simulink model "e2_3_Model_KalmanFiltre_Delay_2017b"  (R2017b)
settings: Solver=ode4  StartTime=0.0  StopTime=100  FixedStep=sampleTime  RelTol=1e-3  EnableMultiTasking=on
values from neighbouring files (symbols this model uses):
  k_d_x = 0.7    [startSimulation.m]
  k_d_y = 0.7    [startSimulation.m]
  k_d_yaw = 0.05    [startSimulation.m]
  k_d_z = 0.05    [startSimulation.m]
  k_i_x = 0.01    [startSimulation.m]
  k_i_y = 0.01    [startSimulation.m]
  k_i_yaw = 0.01    [startSimulation.m]
  k_i_z = 0.01    [startSimulation.m]
  k_p_x = 1    [startSimulation.m]
  k_p_y = 1    [startSimulation.m]
  k_p_yaw = 2    [startSimulation.m]
  k_p_z = 3    [startSimulation.m]
  Kd_RP_AgngleRate = 0.005    [startSimulation.m]
  Kd_YAW_AngleRate = 0.05    [startSimulation.m]
  Ki_RP_AgngleRate = 0.01    [startSimulation.m]
  Ki_YAW_AngleRate = 0.8    [startSimulation.m]
  Kp_RP_AgngleRate = 0.55    [startSimulation.m]
  Kp_RP_ANGLE = 6.5    [startSimulation.m]
  Kp_YAW_AngleRate = 3.2    [startSimulation.m]
  saturation_psi = 2    [startSimulation.m]
  saturation_x = 2    [startSimulation.m]
  saturation_y = 2    [startSimulation.m]
  saturation_z = 2    [startSimulation.m]
  simDT = 0.01    [startSimulation.m]
undefined symbols (not defined in the file or in its folder): DiscIntNeverNeededParam, Earth, earthRadius, KiPitchAttitude, KiRollAttitude, ModelInit, ModelParam, Receive, Send, sigbuilder_block, unidrnd, WGS84
libraries: simulink x26, sharedtransform x3, aerolibtransform2 x3, aerolibfltsims x3, aerolibutil x2, aerolibanimutils x1, shared6dof x1, aerolibatmos2 x1, aerolibconvert2 x1, aerolibobsolete x1, aerolibasang x1, aerolibnav x1
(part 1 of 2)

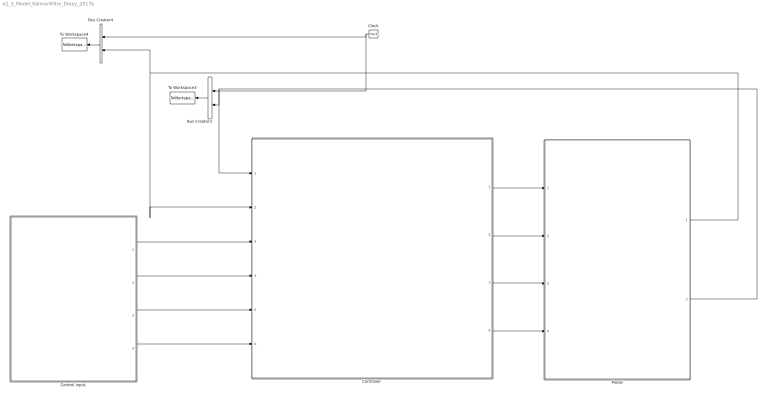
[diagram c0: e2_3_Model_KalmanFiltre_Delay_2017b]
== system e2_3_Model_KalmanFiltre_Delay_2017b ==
  Bus Creator3 : BusCreator  Inputs=2
  Bus Creator4 : BusCreator  Inputs=2
  Clock : Clock
  Control Input : Subsystem
  "Controller " : Subsystem
  Model : Subsystem
  To Workspace3 : ToWorkspace  VariableName=r1_pos_array  SampleTime=-1
  To Workspace4 : ToWorkspace  VariableName=r1_vel_array  SampleTime=-1
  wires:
  Clock/1 -> Bus Creator4/1, Bus Creator3/1
  Bus Creator3/1 -> To Workspace3/1
  Bus Creator4/1 -> To Workspace4/1
  "Controller "/1(Controller Output X) -> Model/1(Commande Input X)
  "Controller "/2(Controller Output Y) -> Model/2(Commande Input Y)
  "Controller "/3(Controller Output H) -> Model/3(Commande Input H)
  "Controller "/4(Controller Output Psi) -> Model/4(Commande Input Psi)
  Control Input/1(ux) -> "Controller "/3(Control input X)
  Control Input/2(uy) -> "Controller "/4(Control input Y)
  Control Input/3(uz) -> "Controller "/5(Control input H)
  Control Input/4(upsi) -> "Controller "/6(Control input Psi)
  Model/2(Output Position) -> "Controller "/1(Feedback Position), Bus Creator3/2
  Model/1(Output Velocity) -> "Controller "/2(Feedback Velocity), Bus Creator4/2

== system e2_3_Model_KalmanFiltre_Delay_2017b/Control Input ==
  Bloc Test Position Fixe : Subsystem
  Bus Creator : BusCreator  Inputs=4
  Demux : Demux
  Simulation Pace : aerolibanimutils/Simulation Pace  SimulationPace=1  SleepMode=MATLAB Thread  OutputPaceError=off  SampleTime=-1
  ux : Outport  VectorParamsAs1DForOutWhenUnconnected=off
  uy : Outport  Port=2  VectorParamsAs1DForOutWhenUnconnected=off
  uz : Outport  Port=3  VectorParamsAs1DForOutWhenUnconnected=off
  upsi : Outport  Port=4  VectorParamsAs1DForOutWhenUnconnected=off
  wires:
  Demux/2 -> uy/1
  Demux/1 -> ux/1
  Bloc Test Position Fixe/2(uy) -> Bus Creator/2
  Demux/3 -> uz/1
  Demux/4 -> upsi/1
  Bloc Test Position Fixe/4(upsi) -> Bus Creator/4
  Bloc Test Position Fixe/3(uz) -> Bus Creator/3
  Bloc Test Position Fixe/1(ux) -> Bus Creator/1
  Bus Creator/1 -> Demux/1

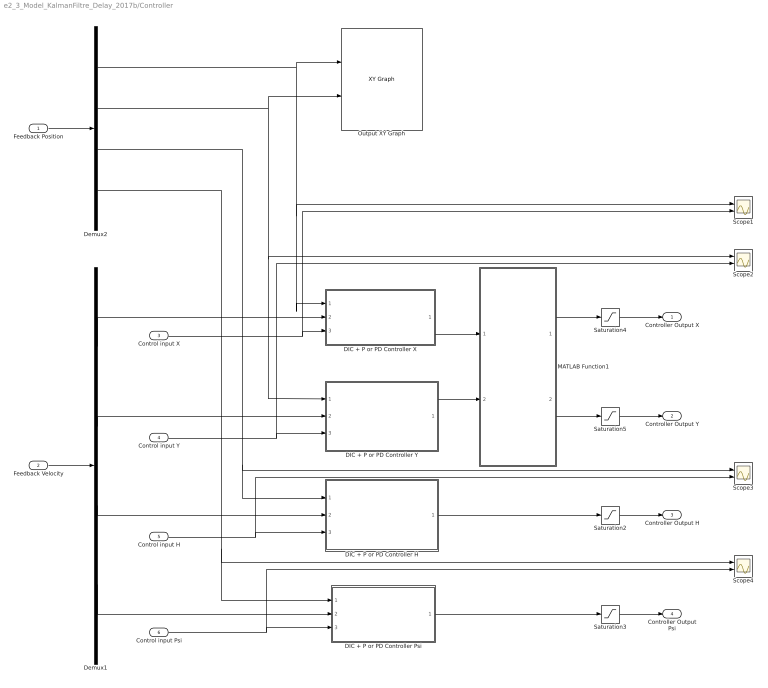
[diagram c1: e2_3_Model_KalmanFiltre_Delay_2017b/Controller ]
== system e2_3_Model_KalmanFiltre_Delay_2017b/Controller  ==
  Feedback Position : Inport
  Feedback Velocity : Inport  Port=2
  Control input X : Inport  Port=3
  Control input Y : Inport  Port=4
  Control input H : Inport  Port=5
  Control input Psi : Inport  Port=6
  DIC + P or PD Controller H : Subsystem
  DIC + P or PD Controller Psi : Subsystem
  DIC + P or PD Controller X : Subsystem
  DIC + P or PD Controller Y : Subsystem
  Demux1 : Demux
  Demux2 : Demux
  MATLAB Function1 : MATLAB Function  TreatAsAtomicUnit=on
  Output XY Graph : simulink/Sinks/XY Graph  Commented=on  xmin=-5  xmax=5  ymin=-5  ymax=5  st=-1
  Saturation2 : Saturate  UpperLimit=saturation_z  LowerLimit=-saturation_z
  Saturation3 : Saturate  UpperLimit=saturation_psi  LowerLimit=-saturation_psi
  Saturation4 : Saturate  UpperLimit=saturation_x  LowerLimit=-saturation_x
  Saturation5 : Saturate  UpperLimit=saturation_y  LowerLimit=-saturation_y
  Scope{1..4} (4 alike) : Scope  NumInputPorts=2
  Controller Output X : Outport  VectorParamsAs1DForOutWhenUnconnected=off
  Controller Output Y : Outport  Port=2  VectorParamsAs1DForOutWhenUnconnected=off
  Controller Output H : Outport  Port=3  VectorParamsAs1DForOutWhenUnconnected=off
  Controller Output Psi : Outport  Port=4  VectorParamsAs1DForOutWhenUnconnected=off
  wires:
  Feedback Position/1 -> Demux2/1
  Feedback Velocity/1 -> Demux1/1
  Demux1/2 -> DIC + P or PD Controller Y/2(Feedback Velocity Y)
  Demux2/3 -> Scope3/1, DIC + P or PD Controller H/1(Feedback Position H)
  Demux1/1 -> DIC + P or PD Controller X/2(Feedback Velocity X)
  Demux1/3 -> DIC + P or PD Controller H/2(Feedback Velocity H)
  Control input X/1 -> Scope1/2, DIC + P or PD Controller X/3(Control Input X)
  Control input H/1 -> Scope3/2, DIC + P or PD Controller H/3(Control Input H)
  Saturation4/1 -> Controller Output X/1
  Saturation5/1 -> Controller Output Y/1
  Saturation2/1 -> Controller Output H/1
  Saturation3/1 -> Controller Output Psi/1
  Control input Y/1 -> Scope2/2, DIC + P or PD Controller Y/3(Control Input Y)
  DIC + P or PD Controller H/1(Controller Output H) -> Saturation2/1
  DIC + P or PD Controller Psi/1(Controller Output Psi) -> Saturation3/1
  Demux2/1 -> Scope1/1, DIC + P or PD Controller X/1(Feedback Position X), Output XY Graph/1
  Demux2/2 -> Scope2/1, DIC + P or PD Controller Y/1(Feedback Position Y), Output XY Graph/2
  Demux2/4 -> Scope4/1, DIC + P or PD Controller Psi/1(Feedback Position Psi)
  Demux1/4 -> DIC + P or PD Controller Psi/2(Feedback Velocity Psi)
  Control input Psi/1 -> Scope4/2, DIC + P or PD Controller Psi/3(Control input Psi)
  MATLAB Function1/2(phi) -> Saturation5/1
  MATLAB Function1/1(theta) -> Saturation4/1
  DIC + P or PD Controller X/1(Controller Output X) -> MATLAB Function1/1(eax)
  DIC + P or PD Controller Y/1(Controller Output Y) -> MATLAB Function1/2(eay)

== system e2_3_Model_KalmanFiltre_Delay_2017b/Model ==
  Commande Input X : Inport
  Commande Input Y : Inport  Port=2
  Commande Input H : Inport  Port=3
  Commande Input Psi : Inport  Port=4
  Bus Creator5 : BusCreator  Inputs=4
  Demux : Demux
  Demux1 : Demux
  Drone_Model_F450 : Subsystem
  Kalman Filtre H : Subsystem
  Kalman Filtre Psi : Subsystem
  Kalman Filtre X : Subsystem
  Kalman Filtre Y : Subsystem
  Output Velocity : Outport  VectorParamsAs1DForOutWhenUnconnected=off
  Output Position : Outport  Port=2  VectorParamsAs1DForOutWhenUnconnected=off
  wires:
  Demux/4 -> Kalman Filtre Psi/1(The system output: Position)
  Bus Creator5/1 -> Output Velocity/1
  Demux/1 -> Kalman Filtre X/1(The system output: Position)
  Kalman Filtre X/1(Out velocity feedback) -> Bus Creator5/1
  Kalman Filtre Psi/1(Out velocity feedback) -> Bus Creator5/4
  Demux/2 -> Kalman Filtre Y/1(The system output: Position)
  Kalman Filtre Y/1(Out velocity feedback) -> Bus Creator5/2
  Kalman Filtre H/1(Out velocity feedback) -> Bus Creator5/3
  Demux/3 -> Kalman Filtre H/1(The system output: Position)
  Demux1/1 -> Kalman Filtre X/2(In2)
  Demux1/2 -> Kalman Filtre Y/2(In2)
  Demux1/3 -> Kalman Filtre H/2(In2)
  Demux1/4 -> Kalman Filtre Psi/2(In2)
  Commande Input H/1 -> Drone_Model_F450/3(u_Thrust_Z_inM/s)
  Drone_Model_F450/1(Position Feedback in m&rad) -> Output Position/1, Demux/1
  Commande Input Psi/1 -> Drone_Model_F450/4(u_YawRate_Psi_inRad/s)
  Commande Input X/1 -> Drone_Model_F450/1(u_Pitch_Theta_X_inRAD_[-0.5,0.5])
  Commande Input Y/1 -> Drone_Model_F450/2(u_Roll_Phi_Y_inRAD_[-0.5,0.5])
  Drone_Model_F450/2(Velocity Feedback in m/s&rad/s) -> Demux1/1

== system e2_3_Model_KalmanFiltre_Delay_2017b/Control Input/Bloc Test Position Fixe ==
  Band-Limited White Noise : simulink/Sources/Band-Limited White Noise  Cov=[0.01]  Ts=simDT  seed=unidrnd(20000)
  Constant2 : Constant
  Gain : Gain  Gain=0.01
  Signal Builder : Subsystem  Tag=STV Subsys  LoadFcn=sigbuilder_block('load');  StartFcn=sigbuilder_block('start');  StopFcn=sigbuilder_block('stop');  ClipboardFcn=sigbuilder_block('clipboard');  mask(Sigbuilder block){tuvar=[0:10]}
      mask help: Simulink:masks:SigbuilderBlock_MD
      mask init:
      | if ~strcmp(get_param(bdroot(gcbh),'SimulationStatus'),'stopped') tuvar = sigbuilder_block('maskInit'); end
  Sine Wave : Sin  Frequency=0.5  SampleTime=0
  Slider Gain1 : simulink/Math Operations/Slider Gain  gain=1  low=-10  high=10
  Slider Gain2 : simulink/Math Operations/Slider Gain  gain=0  low=-10  high=10
  Slider Gain3 : simulink/Math Operations/Slider Gain  gain=0  low=-2  high=2
  Slider Gain4 : simulink/Math Operations/Slider Gain  gain=0  low=-2  high=2
  Step : Step  Time=5  SampleTime=0
  Sum : Sum  Inputs=|++
  Sum1 : Sum  Inputs=|++
  ux : Outport  VectorParamsAs1DForOutWhenUnconnected=off
  uy : Outport  Port=2  VectorParamsAs1DForOutWhenUnconnected=off
  uz : Outport  Port=3  VectorParamsAs1DForOutWhenUnconnected=off
  upsi : Outport  Port=4  VectorParamsAs1DForOutWhenUnconnected=off
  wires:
  Slider Gain1/1 -> ux/1
  Slider Gain2/1 -> uy/1
  Slider Gain3/1 -> uz/1
  Slider Gain4/1 -> upsi/1
  Sum/1 -> Slider Gain3/1
  Constant2/1 -> Sum/1
  Band-Limited White Noise/1 -> Gain/1
  Sine Wave/1 -> Sum1/1
  Gain/1 -> Sum1/2
  Sum1/1 -> Slider Gain2/1, Slider Gain1/1, Slider Gain4/1, Sum/2

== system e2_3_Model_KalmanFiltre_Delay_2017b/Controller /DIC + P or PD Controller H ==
  Feedback Position H : Inport
  Feedback Velocity H : Inport  Port=2
  Control Input H : Inport  Port=3
  Derivative : Derivative
  Integrator : Integrator
  Sum1 : Sum  Inputs=|-+
  Sum10 : Sum  Inputs=|+-
  Sum9 : Sum  Inputs=+++|
  Vx-d2 : Gain  Gain=k_d_z
  kxp3 : Gain  Gain=k_p_z
  kxp4 : Gain  Gain=k_i_z
  Controller Output H : Outport  VectorParamsAs1DForOutWhenUnconnected=off
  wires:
  Sum9/1 -> Controller Output H/1
  Sum10/1 -> kxp3/1, Integrator/1
  kxp3/1 -> Sum9/2
  Vx-d2/1 -> Sum9/1
  Feedback Velocity H/1 -> Sum1/1
  Sum1/1 -> Vx-d2/1
  Integrator/1 -> kxp4/1
  kxp4/1 -> Sum9/3
  Control Input H/1 -> Sum10/1, Derivative/1
  Feedback Position H/1 -> Sum10/2
  Derivative/1 -> Sum1/2

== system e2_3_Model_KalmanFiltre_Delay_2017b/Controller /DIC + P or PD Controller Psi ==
  Feedback Position Psi : Inport
  Feedback Velocity Psi : Inport  Port=2
  Control input Psi : Inport  Port=3
  Derivative : Derivative
  Gain1 : Gain  Gain=k_p_yaw
  Gain4 : Gain  Gain=k_d_yaw
  Integrator : Integrator
  Sum1 : Sum  Inputs=|-+
  Sum10 : Sum  Inputs=|+-
  Sum9 : Sum  Inputs=+++|
  kxp2 : Gain  Gain=k_i_yaw
  Controller Output Psi : Outport  VectorParamsAs1DForOutWhenUnconnected=off
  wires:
  Sum9/1 -> Controller Output Psi/1
  kxp2/1 -> Sum9/3
  Control input Psi/1 -> Sum10/1, Derivative/1
  Gain4/1 -> Sum9/1
  Sum10/1 -> Gain1/1, Integrator/1
  Integrator/1 -> kxp2/1
  Feedback Velocity Psi/1 -> Sum1/1
  Sum1/1 -> Gain4/1
  Gain1/1 -> Sum9/2
  Derivative/1 -> Sum1/2
  Feedback Position Psi/1 -> Sum10/2

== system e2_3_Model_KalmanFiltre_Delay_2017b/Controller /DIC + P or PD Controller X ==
  Feedback Position X : Inport
  Feedback Velocity X : Inport  Port=2
  Control Input X : Inport  Port=3
  PID1 : Subsystem
  Sum3 : Sum  Inputs=|+-
  Sum4 : Sum  Inputs=|+-
  roll_attitude2 : simulink/Continuous/PID Controller  Controller=P  Form=Parallel  TimeDomain=Discrete-time  SampleTime=-1  IntegratorMethod=Forward Euler  FilterMethod=Forward Euler  ControllerParametersSource=internal  P=1  I=KiRollAttitude  D=0.01  UseFilter=on  N=100  TunerSelectOption=Transfer Function Based (PID Tuner App)  InitialConditionSource=internal  InitialConditionForIntegrator=0  InitialConditionForFilter=0  DifferentiatorICPrevScaledInput=0  ExternalReset=none  TrackingMode=off  Kt=1  LimitOutput=on  UpperSaturationLimit=100  LowerSaturationLimit=-100  LinearizeAsGain=on  AntiWindupMode=back-calculation  Kb=1  POutMin=[]  POutMax=[]  IOutMin=[]  IOutMax=[]  DOutMin=[]  DOutMax=[]  NOutMin=[]  NOutMax=[]  SumOutMin=[]  SumOutMax=[]  SaturationOutMin=[]  SaturationOutMax=[]  PParamMin=[]  PParamMax=[]  IParamMin=[]  IParamMax=[]  DParamMin=[]  DParamMax=[]  NParamMin=[]  NParamMax=[]  KbParamMin=[]  KbParamMax=[]  KtParamMin=[]  KtParamMax=[]  KbOutMin=[]  KbOutMax=[]  KtOutMin=[]  KtOutMax=[]  IntegratorOutMin=[]  IntegratorOutMax=[]  FilterOutMin=[]  FilterOutMax=[]  SumI1OutMin=[]  SumI1OutMax=[]  SumI2OutMin=[]  SumI2OutMax=[]  SumI3OutMin=[]  SumI3OutMax=[]  SumDOutMin=[]  SumDOutMax=[]  DifferentiatorOutMin=[]  DifferentiatorOutMax=[]  FilterDiffOutCoefMin=[]  FilterDiffOutCoefMax=[]  ReciprocalOutMin=[]  ReciprocalOutMax=[]  SumDenOutMin=[]  SumDenOutMax=[]  SumNumOutMin=[]  SumNumOutMax=[]  DivideOutMin=[]  DivideOutMax=[]  IntegratorContinuousStateAttributes=''  IntegratorStateMustResolveToSignalObject=off  IntegratorRTWStateStorageClass=Auto  FilterContinuousStateAttributes=''  FilterStateMustResolveToSignalObject=off  FilterRTWStateStorageClass=Auto  InitialConditionSetting=State (most efficient)
  Controller Output X : Outport  VectorParamsAs1DForOutWhenUnconnected=off
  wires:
  roll_attitude2/1 -> Sum4/1
  Sum3/1 -> roll_attitude2/1
  Sum4/1 -> PID1/1(x)
  PID1/1(y) -> Controller Output X/1
  Feedback Velocity X/1 -> Sum4/2
  Control Input X/1 -> Sum3/1
  Feedback Position X/1 -> Sum3/2

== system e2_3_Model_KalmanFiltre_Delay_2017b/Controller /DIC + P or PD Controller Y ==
  Feedback Position Y : Inport
  Feedback Velocity Y : Inport  Port=2
  Control Input Y : Inport  Port=3
  PID2 : Subsystem
  Sum : Sum  Inputs=|+-
  Sum2 : Sum  Inputs=|+-
  roll_attitude : simulink/Continuous/PID Controller  Controller=P  Form=Parallel  TimeDomain=Discrete-time  SampleTime=-1  IntegratorMethod=Forward Euler  FilterMethod=Forward Euler  ControllerParametersSource=internal  P=1  I=KiRollAttitude  D=0.01  UseFilter=on  N=100  TunerSelectOption=Transfer Function Based (PID Tuner App)  InitialConditionSource=internal  InitialConditionForIntegrator=0  InitialConditionForFilter=0  DifferentiatorICPrevScaledInput=0  ExternalReset=none  TrackingMode=off  Kt=1  LimitOutput=on  UpperSaturationLimit=1  LowerSaturationLimit=-1  LinearizeAsGain=on  AntiWindupMode=back-calculation  Kb=1  POutMin=[]  POutMax=[]  IOutMin=[]  IOutMax=[]  DOutMin=[]  DOutMax=[]  NOutMin=[]  NOutMax=[]  SumOutMin=[]  SumOutMax=[]  SaturationOutMin=[]  SaturationOutMax=[]  PParamMin=[]  PParamMax=[]  IParamMin=[]  IParamMax=[]  DParamMin=[]  DParamMax=[]  NParamMin=[]  NParamMax=[]  KbParamMin=[]  KbParamMax=[]  KtParamMin=[]  KtParamMax=[]  KbOutMin=[]  KbOutMax=[]  KtOutMin=[]  KtOutMax=[]  IntegratorOutMin=[]  IntegratorOutMax=[]  FilterOutMin=[]  FilterOutMax=[]  SumI1OutMin=[]  SumI1OutMax=[]  SumI2OutMin=[]  SumI2OutMax=[]  SumI3OutMin=[]  SumI3OutMax=[]  SumDOutMin=[]  SumDOutMax=[]  DifferentiatorOutMin=[]  DifferentiatorOutMax=[]  FilterDiffOutCoefMin=[]  FilterDiffOutCoefMax=[]  ReciprocalOutMin=[]  ReciprocalOutMax=[]  SumDenOutMin=[]  SumDenOutMax=[]  SumNumOutMin=[]  SumNumOutMax=[]  DivideOutMin=[]  DivideOutMax=[]  IntegratorContinuousStateAttributes=''  IntegratorStateMustResolveToSignalObject=off  IntegratorRTWStateStorageClass=Auto  FilterContinuousStateAttributes=''  FilterStateMustResolveToSignalObject=off  FilterRTWStateStorageClass=Auto  InitialConditionSetting=State (most efficient)
  Controller Output Y : Outport  VectorParamsAs1DForOutWhenUnconnected=off
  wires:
  Sum/1 -> roll_attitude/1
  roll_attitude/1 -> Sum2/1
  Sum2/1 -> PID2/1(x)
  Feedback Position Y/1 -> Sum/2
  Feedback Velocity Y/1 -> Sum2/2
  Control Input Y/1 -> Sum/1
  PID2/1(y) -> Controller Output Y/1

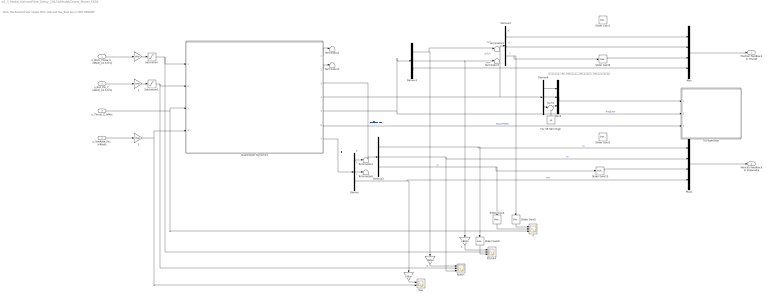
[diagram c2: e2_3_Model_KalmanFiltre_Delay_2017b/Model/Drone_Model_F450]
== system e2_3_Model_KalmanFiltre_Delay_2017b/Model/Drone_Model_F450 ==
  note: 偏航角度值介于[-180,180]之间，超过180度时自动变为-180度之后再继续增加。
  note: Here, the desired Euler angles Pitch, Roll and Yaw_Rate are in UNIT DEGREE!
  note: z
  note: y
  note: x
  note: r
  note: q
  note: p
  note: yaw
  note: pitch
  note: roll
  u_Pitch_Theta_X_inRAD_[-0.5,0.5] : Inport
  u_Roll_Phi_Y_inRAD_[-0.5,0.5] : Inport  Port=2
  u_Thrust_Z_inM/s : Inport  Port=3
  u_YawRate_Psi_inRad/s : Inport  Port=4
  " " : Gain  Gain=180/pi
  "  " : Gain  Gain=180/pi
  "  1" : Gain  Gain=180/pi
  "  2" : Gain  Gain=180/pi
  " 1" : Gain  Gain=180/pi
  " 2" : Gain  Gain=180/pi
  Demux{,1..4} (5 alike) : Demux  Outputs=3
  For VR 50m High : Constant  Value=-50
  Mux : Mux
  Mux1 : Mux
  Mux2 : Mux  Inputs=3
  Pitch&X : Scope  NumInputPorts=3
  Quadcopter Dynamics : Subsystem
  Roll&Y : Scope  NumInputPorts=3
  Saturation : Saturate  UpperLimit=15  LowerLimit=-15
  Saturation1 : Saturate  UpperLimit=15  LowerLimit=-15
  Slider Gain{1..2,4..6,9,13} (7 alike) : simulink/Math Operations/Slider Gain  gain=-1  low=-5  high=5
  Sum1 : Sum  Inputs=|++
  Terminator{1,3..7} (6 alike) : Terminator
  To FlightGear : Subsystem
  Yaw : Scope  NumInputPorts=2
  Z : Scope  NumInputPorts=3
  Position Feedback in m&rad : Outport  VectorParamsAs1DForOutWhenUnconnected=off
  Velocity Feedback in m/s&rad/s : Outport  Port=2  VectorParamsAs1DForOutWhenUnconnected=off
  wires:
  " 2"/1 -> Quadcopter Dynamics/4(u_Yaw_rate), Yaw/2
  "  1"/1 -> Pitch&X/1
  " 1"/1 -> Saturation1/1
  Slider Gain9/1 -> Mux/3
  Slider Gain13/1 -> Mux1/3
  " "/1 -> Saturation/1
  Demux2/2 -> Mux/2
  u_Pitch_Theta_X_inRAD_[-0.5,0.5]/1 -> " "/1
  Slider Gain4/1 -> Z/2
  Demux4/1 -> Mux2/1
  Mux2/1 -> To FlightGear/1(PosE)
  Demux4/3 -> Sum1/1
  Sum1/1 -> Mux2/3
  Slider Gain6/1 -> Pitch&X/3
  Demux4/2 -> Mux2/2
  Slider Gain5/1 -> Z/1
  For VR 50m High/1 -> Sum1/2
  "  "/1 -> Yaw/1
  "  2"/1 -> Roll&Y/1
  u_YawRate_Psi_inRad/s/1 -> " 2"/1
  Demux1/2 -> "  1"/1, Terminator7/1
  Demux/2 -> Terminator6/1
  Demux3/1 -> Mux1/1, Slider Gain6/1  "vx"
  Quadcopter Dynamics/7(AngRateB) -> Demux/1  "转动角速度"
  Quadcopter Dynamics/6(MotorRPMS) -> To FlightGear/3(MotorPWMs)  "MotorPWMs"
  Mux/1 -> Position Feedback in m&rad/1
  Quadcopter Dynamics/5(AngEuler) -> Demux1/1, To FlightGear/2(AngEular)  "AngEular"
  Mux1/1 -> Velocity Feedback in m/s&rad/s/1
  Demux3/3 -> Slider Gain13/1, Slider Gain4/1  "vz"
  Quadcopter Dynamics/3(VelE) -> Demux3/1  "地球坐标系下速度向量"
  u_Roll_Phi_Y_inRAD_[-0.5,0.5]/1 -> " 1"/1
  Demux2/3 -> Slider Gain9/1, Slider Gain5/1
  Quadcopter Dynamics/4(PosE) -> Demux2/1, Demux4/1
  Demux/3 -> "  "/1, Mux1/4  "raw"
  Demux1/3 -> Mux/4
  Quadcopter Dynamics/2(MavHILGPS) -> Terminator3/1
  Quadcopter Dynamics/1(MavHILSensor) -> Terminator1/1
  Demux3/2 -> Mux1/2, Roll&Y/3  "vy"
  Demux/1 -> Terminator4/1
  u_Thrust_Z_inM/s/1 -> Quadcopter Dynamics/3(u_Thrust), Z/3
  Demux1/1 -> Terminator5/1, "  2"/1
  Saturation/1 -> Quadcopter Dynamics/1(u_Pitch), Pitch&X/2
  Saturation1/1 -> Quadcopter Dynamics/2(u_Roll), Roll&Y/2
  Demux2/1 -> Mux/1

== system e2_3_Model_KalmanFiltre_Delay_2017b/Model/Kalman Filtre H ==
  The system output: Position : Inport
  In2 : Inport  Port=2
  Demux : Demux  Outputs=9
  Error : Scope
  Kalman Filtre H : Subsystem
  Kalman Filtre for getting the velocity H : MATLAB Function  TreatAsAtomicUnit=on  SystemSampleTime=0.01
  Manual Switch1 : ManualSwitch  CurrentSetting=0
  Memory block for resolving the 'algebraic loop' problem : Memory
  Scope2 : Scope
  Scope4 : Scope  NumInputPorts=8
  Sum : Sum  Inputs=-+|
  The comparison of velocity signal between 'Derivative' and 'Kalman filtering' : Scope  NumInputPorts=2
  Unit Delay1 : UnitDelay  SampleTime=-1  HasFrameUpgradeWarning=on
  Unit Delay7 : UnitDelay  SampleTime=-1  HasFrameUpgradeWarning=on
  Unit Delay8 : UnitDelay  SampleTime=-1  HasFrameUpgradeWarning=on
  Zero-Order Hold1 : ZeroOrderHold  SampleTime=-1
  Out velocity feedback : Outport  VectorParamsAs1DForOutWhenUnconnected=off
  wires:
  Kalman Filtre for getting the velocity H/1(Covariance_matrice) -> Scope2/1
  Kalman Filtre for getting the velocity H/2(X_Kalmanfiltred) -> Memory block for resolving the 'algebraic loop' problem/1
  Memory block for resolving the 'algebraic loop' problem/1 -> Demux/1
  Zero-Order Hold1/1 -> Kalman Filtre for getting the velocity H/1(Mesurement_Velocity)
  Manual Switch1/1 -> Out velocity feedback/1
  Demux/1 -> Scope4/1
  The system output: Position/1 -> Kalman Filtre H/1(The system output: Position), Manual Switch1/1, Unit Delay7/1
  Demux/2 -> Scope4/2
  Demux/3 -> Scope4/3
  Demux/4 -> Scope4/4
  Demux/5 -> Scope4/5
  Unit Delay8/1 -> Zero-Order Hold1/1
  Demux/6 -> Scope4/6
  Demux/7 -> Scope4/8
  Demux/8 -> Sum/1, The comparison of velocity signal between 'Derivative' and 'Kalman filtering'/1, Manual Switch1/2
  Demux/9 -> Scope4/7
  In2/1 -> The comparison of velocity signal between 'Derivative' and 'Kalman filtering'/2
  Unit Delay7/1 -> Unit Delay1/1
  Unit Delay1/1 -> Unit Delay8/1
  Sum/1 -> Error/1
  Kalman Filtre H/1(Out velocity feedback) -> Sum/2

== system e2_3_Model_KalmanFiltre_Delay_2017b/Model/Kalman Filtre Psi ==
  The system output: Position : Inport
  In2 : Inport  Port=2
  Demux : Demux  Outputs=9
  Error : Scope
  Kalman Filtre Psi : Subsystem
  Kalman Filtre for getting the velocity Psi : MATLAB Function  TreatAsAtomicUnit=on  SystemSampleTime=0.01
  Manual Switch1 : ManualSwitch  CurrentSetting=0
  Memory block for resolving the 'algebraic loop' problem : Memory
  Scope2 : Scope
  Scope4 : Scope  NumInputPorts=8
  Sum : Sum  Inputs=-+|
  The comparison of velocity signal between 'Derivative' and 'Kalman filtering' : Scope  NumInputPorts=2
  Unit Delay1 : UnitDelay  SampleTime=-1  HasFrameUpgradeWarning=on
  Unit Delay7 : UnitDelay  SampleTime=-1  HasFrameUpgradeWarning=on
  Unit Delay8 : UnitDelay  SampleTime=-1  HasFrameUpgradeWarning=on
  Zero-Order Hold1 : ZeroOrderHold  SampleTime=-1
  Out velocity feedback : Outport  VectorParamsAs1DForOutWhenUnconnected=off
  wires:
  Kalman Filtre for getting the velocity Psi/1(Covariance_matrice) -> Scope2/1
  Kalman Filtre for getting the velocity Psi/2(X_Kalmanfiltred) -> Memory block for resolving the 'algebraic loop' problem/1
  Memory block for resolving the 'algebraic loop' problem/1 -> Demux/1
  Zero-Order Hold1/1 -> Kalman Filtre for getting the velocity Psi/1(Mesurement_Velocity)
  Manual Switch1/1 -> Out velocity feedback/1
  Demux/1 -> Scope4/1
  The system output: Position/1 -> Kalman Filtre Psi/1(The system output: Position), Manual Switch1/1, Unit Delay7/1
  Demux/2 -> Scope4/2
  Demux/3 -> Scope4/3
  Demux/4 -> Scope4/4
  Demux/5 -> Scope4/5
  Unit Delay8/1 -> Zero-Order Hold1/1
  Demux/6 -> Scope4/6
  Demux/7 -> Scope4/8
  Demux/8 -> Sum/1, The comparison of velocity signal between 'Derivative' and 'Kalman filtering'/1, Manual Switch1/2
  Demux/9 -> Scope4/7
  In2/1 -> The comparison of velocity signal between 'Derivative' and 'Kalman filtering'/2
  Unit Delay7/1 -> Unit Delay1/1
  Unit Delay1/1 -> Unit Delay8/1
  Sum/1 -> Error/1
  Kalman Filtre Psi/1(Out velocity feedback) -> Sum/2

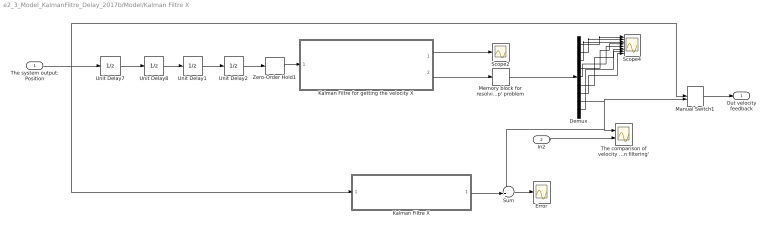
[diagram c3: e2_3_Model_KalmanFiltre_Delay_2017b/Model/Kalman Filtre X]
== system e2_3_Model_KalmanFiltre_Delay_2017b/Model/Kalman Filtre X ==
  The system output: Position : Inport
  In2 : Inport  Port=2
  Demux : Demux  Outputs=9
  Error : Scope
  Kalman Filtre X : Subsystem
  Kalman Filtre for getting the velocity X : MATLAB Function  TreatAsAtomicUnit=on  SystemSampleTime=0.01
  Manual Switch1 : ManualSwitch  CurrentSetting=0
  Memory block for resolving the 'algebraic loop' problem : Memory
  Scope2 : Scope
  Scope4 : Scope  NumInputPorts=8
  Sum : Sum  Inputs=-+|
  The comparison of velocity signal between 'Derivative' and 'Kalman filtering' : Scope  NumInputPorts=2
  Unit Delay{1..2,7..8} (4 alike) : UnitDelay  SampleTime=-1  HasFrameUpgradeWarning=on
  Zero-Order Hold1 : ZeroOrderHold  SampleTime=-1
  Out velocity feedback : Outport  VectorParamsAs1DForOutWhenUnconnected=off
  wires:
  Kalman Filtre for getting the velocity X/1(Covariance_matrice) -> Scope2/1
  Kalman Filtre for getting the velocity X/2(X_Kalmanfiltred) -> Memory block for resolving the 'algebraic loop' problem/1
  Memory block for resolving the 'algebraic loop' problem/1 -> Demux/1
  Zero-Order Hold1/1 -> Kalman Filtre for getting the velocity X/1(Mesurement_Velocity)
  Manual Switch1/1 -> Out velocity feedback/1
  Demux/1 -> Scope4/1
  The system output: Position/1 -> Kalman Filtre X/1(The system output: Position), Manual Switch1/1, Unit Delay7/1
  Demux/2 -> Scope4/2
  Demux/3 -> Scope4/3
  Demux/4 -> Scope4/4
  Demux/5 -> Scope4/5
  Unit Delay7/1 -> Unit Delay8/1
  Unit Delay8/1 -> Unit Delay1/1
  Demux/6 -> Scope4/6
  Demux/7 -> Scope4/8
  Demux/8 -> Sum/1, The comparison of velocity signal between 'Derivative' and 'Kalman filtering'/1, Manual Switch1/2
  Demux/9 -> Scope4/7
  In2/1 -> The comparison of velocity signal between 'Derivative' and 'Kalman filtering'/2
  Unit Delay1/1 -> Unit Delay2/1
  Unit Delay2/1 -> Zero-Order Hold1/1
  Kalman Filtre X/1(Out velocity feedback) -> Sum/2
  Sum/1 -> Error/1

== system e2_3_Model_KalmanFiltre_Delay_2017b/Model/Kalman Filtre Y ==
  The system output: Position : Inport
  In2 : Inport  Port=2
  Demux : Demux  Outputs=9
  Error : Scope
  Kalman Filtre Y : Subsystem
  Kalman Filtre for getting the velocity Y : MATLAB Function  TreatAsAtomicUnit=on  SystemSampleTime=0.01
  Manual Switch1 : ManualSwitch  CurrentSetting=0
  Memory block for resolving the 'algebraic loop' problem : Memory
  Scope2 : Scope
  Scope4 : Scope  NumInputPorts=8
  Sum : Sum  Inputs=-+|
  The comparison of velocity signal between 'Derivative' and 'Kalman filtering' : Scope  NumInputPorts=2
  Unit Delay{1..2,7..8} (4 alike) : UnitDelay  SampleTime=-1  HasFrameUpgradeWarning=on
  Zero-Order Hold1 : ZeroOrderHold  SampleTime=-1
  Out velocity feedback : Outport  VectorParamsAs1DForOutWhenUnconnected=off
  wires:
  Kalman Filtre for getting the velocity Y/1(Covariance_matrice) -> Scope2/1
  Kalman Filtre for getting the velocity Y/2(X_Kalmanfiltred) -> Memory block for resolving the 'algebraic loop' problem/1
  Memory block for resolving the 'algebraic loop' problem/1 -> Demux/1
  Zero-Order Hold1/1 -> Kalman Filtre for getting the velocity Y/1(Mesurement_Velocity)
  Manual Switch1/1 -> Out velocity feedback/1
  Demux/1 -> Scope4/1
  The system output: Position/1 -> Kalman Filtre Y/1(The system output: Position), Unit Delay7/1, Manual Switch1/1
  Demux/2 -> Scope4/2
  Demux/3 -> Scope4/3
  Demux/4 -> Scope4/4
  Demux/5 -> Scope4/5
  Unit Delay2/1 -> Zero-Order Hold1/1
  Demux/6 -> Scope4/6
  Demux/7 -> Scope4/8
  Demux/8 -> Sum/1, The comparison of velocity signal between 'Derivative' and 'Kalman filtering'/1, Manual Switch1/2
  Demux/9 -> Scope4/7
  In2/1 -> The comparison of velocity signal between 'Derivative' and 'Kalman filtering'/2
  Unit Delay1/1 -> Unit Delay2/1
  Unit Delay8/1 -> Unit Delay1/1
  Unit Delay7/1 -> Unit Delay8/1
  Sum/1 -> Error/1
  Kalman Filtre Y/1(Out velocity feedback) -> Sum/2

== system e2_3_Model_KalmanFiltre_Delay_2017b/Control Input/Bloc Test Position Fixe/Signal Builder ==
  Demux : Demux  Tag=STV Demux  Outputs=1
  FromWs : FromWorkspace  Tag=STV FromWs  VariableName=tuvar
  Signal 2 : Outport  Tag=STV Outport  VectorParamsAs1DForOutWhenUnconnected=off
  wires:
  FromWs/1 -> Demux/1
  Demux/1 -> Signal 2/1

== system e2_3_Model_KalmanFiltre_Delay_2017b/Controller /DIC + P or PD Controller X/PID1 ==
  x : Inport
  Discrete Derivative : simulink/Discrete/Discrete Derivative  gainval=1.0  ICPrevScaledInput=0.0  OutMin=-5  OutMax=5  OutDataType=fixdt(1, 16)  OutScaling=2^-10  DoSatur=off
  Discrete-Time Integrator : DiscreteIntegrator  InitialConditionSetting=State (most efficient)  SampleTime=-1  LimitOutput=on  UpperSaturationLimit=5  LowerSaturationLimit=-5  ICPrevOutput=DiscIntNeverNeededParam  ICPrevScaledInput=DiscIntNeverNeededParam
  Sum : Sum  Inputs=+++  OutMin=-10  OutMax=10
  Vx-d3 : Gain  Gain=k_d_x
  kxp2 : Gain  Gain=k_i_x
  kxp3 : Gain  Gain=k_p_x
  y : Outport  InitialOutput=0  VectorParamsAs1DForOutWhenUnconnected=off
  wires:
  x/1 -> Vx-d3/1, kxp2/1, kxp3/1
  kxp2/1 -> Discrete-Time Integrator/1
  Vx-d3/1 -> Discrete Derivative/1
  kxp3/1 -> Sum/1
  Sum/1 -> y/1
  Discrete Derivative/1 -> Sum/3
  Discrete-Time Integrator/1 -> Sum/2

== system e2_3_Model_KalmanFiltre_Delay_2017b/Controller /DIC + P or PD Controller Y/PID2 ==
  x : Inport
  Discrete Derivative : simulink/Discrete/Discrete Derivative  gainval=1.0  ICPrevScaledInput=0.0  OutMin=[]  OutMax=[]  OutDataType=fixdt(1, 16)  OutScaling=2^-10  DoSatur=off
  Discrete-Time Integrator : DiscreteIntegrator  InitialConditionSetting=State (most efficient)  SampleTime=-1  LimitOutput=on  UpperSaturationLimit=10  LowerSaturationLimit=-10  ICPrevOutput=DiscIntNeverNeededParam  ICPrevScaledInput=DiscIntNeverNeededParam
  Sum : Sum  Inputs=+++  OutMin=-10  OutMax=10
  Vx-d2 : Gain  Gain=k_d_y
  kxp2 : Gain  Gain=k_p_y
  kxp3 : Gain  Gain=k_i_y
  y : Outport  InitialOutput=0  VectorParamsAs1DForOutWhenUnconnected=off
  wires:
  x/1 -> kxp2/1, kxp3/1, Vx-d2/1
  kxp3/1 -> Discrete-Time Integrator/1
  Vx-d2/1 -> Discrete Derivative/1
  kxp2/1 -> Sum/1
  Sum/1 -> y/1
  Discrete Derivative/1 -> Sum/3
  Discrete-Time Integrator/1 -> Sum/2

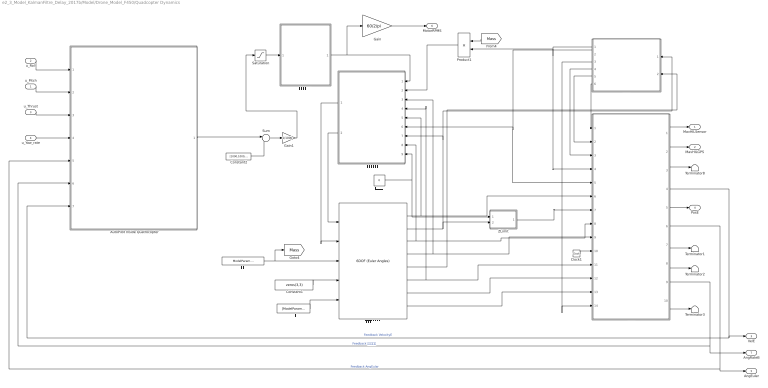
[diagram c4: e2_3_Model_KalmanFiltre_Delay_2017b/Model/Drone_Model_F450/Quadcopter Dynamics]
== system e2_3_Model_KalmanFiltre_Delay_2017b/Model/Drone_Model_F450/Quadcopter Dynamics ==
  u_Pitch : Inport  OutDataTypeStr=double  PortDimensions=1
  u_Roll : Inport  Port=2  OutDataTypeStr=double  PortDimensions=1
  u_Thrust : Inport  Port=3  OutDataTypeStr=double  PortDimensions=1
  u_Yaw_rate : Inport  Port=4  OutDataTypeStr=double  PortDimensions=1
  AutoPilot Inside Quatrocopter : Subsystem
  Clock1 : Clock
  Constant1 : Constant  Value=zeros(3,3)
  Constant2 : Constant  Value=[1000,1000,1000,1000]
  Gain : Gain  Gain=60/2/pi
  Gain1 : Gain  Gain=1/1000
  Product1 : Product
  Saturation : Saturate  UpperLimit=1  LowerLimit=0
  Sum : Sum  Inputs=|+-
  Terminator{1..3,8} (4 alike) : Terminator
  ZLimit : MATLAB Function  TreatAsAtomicUnit=on
  六自由度刚体模型 : shared6dof/6DOF (Euler Angles)  units=Metric (MKS)  mtype=Custom Variable  rep=Quaternion  xme_0=ModelInit.PosE  Vm_0=ModelInit.VelB  eul_0=ModelInit.AngEuler  pm_0=ModelInit.RateB  mass_0=1.0  mass_e=0.5  mass_f=2.0  inertia=eye(3)  inertia_e=eye(3)  inertia_f=2*eye(3)  k_quat=1.0  vre_flag=off  abi_flag=off
  力与力矩模型 : Subsystem
  地形高度 : Constant  Value=0
  环境模型l : Subsystem
  电机动态模型 : Subsystem
  质量 : Constant  Value=ModelParam.uavMass
  转动惯量 : Constant  Value=[ModelParam.uavJxx,0,0;0,ModelParam.uavJyy,0;0,0,ModelParam.uavJzz]
  输出接口 : Subsystem
  MavHILSensor : Outport  VectorParamsAs1DForOutWhenUnconnected=off
  MavHILGPS : Outport  Port=2  VectorParamsAs1DForOutWhenUnconnected=off
  VelE : Outport  Port=3  VectorParamsAs1DForOutWhenUnconnected=off
  PosE : Outport  Port=4  VectorParamsAs1DForOutWhenUnconnected=off
  AngEuler : Outport  Port=5  VectorParamsAs1DForOutWhenUnconnected=off
  MotorRPMS : Outport  Port=6  VectorParamsAs1DForOutWhenUnconnected=off
  AngRateB : Outport  Port=7  VectorParamsAs1DForOutWhenUnconnected=off
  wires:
  [Mass] -> Product1/1
  Product1/1 -> 力与力矩模型/2(mg)
  环境模型l/2(Windb) -> 力与力矩模型/6(Vb), 输出接口/5(Wind_b)
  力与力矩模型/2(Fb) -> 六自由度刚体模型/1
  质量/1 -> [Mass], 六自由度刚体模型/3
  Constant1/1 -> 六自由度刚体模型/4
  六自由度刚体模型/5 -> 环境模型l/2(Vb)
  六自由度刚体模型/6 -> 力与力矩模型/4(wb), 输出接口/11(wb)
  六自由度刚体模型/1 -> 力与力矩模型/5(Ve), 输出接口/6(Ve)
  六自由度刚体模型/4 -> 力与力矩模型/3(DCM), 输出接口/9(DCMbe)
  六自由度刚体模型/2 -> ZLimit/2(xe), 力与力矩模型/7(Xe), 环境模型l/1(Xe)
  环境模型l/1(gravity) -> 输出接口/4(gravity), Product1/2
  Clock1/1 -> 输出接口/10(clock)
  环境模型l/3(Rho) -> 输出接口/14(rho)
  环境模型l/4(TempC) -> 输出接口/3(TempC)
  环境模型l/5(AirPressure) -> 输出接口/2(AirPressure)
  环境模型l/6(PosGPS) -> 输出接口/1(PosGPSin)
  六自由度刚体模型/3 -> 力与力矩模型/8(AngEular), 输出接口/8(Euler)
  六自由度刚体模型/7 -> 输出接口/12(dwdt)
  六自由度刚体模型/8 -> 输出接口/13(Ab)
  输出接口/3(SysTime) -> Terminator8/1
  输出接口/4(VelE) -> VelE/1, AutoPilot Inside Quatrocopter/7(Feedback_Velocity_Earth)  "Feedback VelocityE"
  输出接口/5(PosE) -> PosE/1
  输出接口/7(AngQuatern) -> Terminator1/1
  输出接口/8(PosGPS) -> Terminator2/1
  输出接口/10(AccB) -> Terminator3/1
  输出接口/1(MavLinkSensorData) -> MavHILSensor/1
  输出接口/2(MavLinkGPSData) -> MavHILGPS/1
  电机动态模型/1(MotorRads) -> 力与力矩模型/1(MotorRads), Gain/1
  Sum/1 -> Gain1/1
  力与力矩模型/1(Mb) -> 六自由度刚体模型/2
  Gain/1 -> MotorRPMS/1
  地形高度/1 -> 力与力矩模型/9("tZ "), ZLimit/1(zt)
  ZLimit/1(Xee) -> 输出接口/7(Xe)
  转动惯量/1 -> 六自由度刚体模型/5
  Constant2/1 -> Sum/2
  AutoPilot Inside Quatrocopter/1(Output PWM) -> Sum/1
  Gain1/1 -> Saturation/1
  Saturation/1 -> 电机动态模型/1(inPWMs)
  输出接口/6(AngEuler) -> AngEuler/1, AutoPilot Inside Quatrocopter/5(Feedback_AngEular)  "Feedback AngEular"
  输出接口/9(RateB) -> AngRateB/1, AutoPilot Inside Quatrocopter/6(Feedback_AngEular_Rate)  "Feedback 转动角速度"
  u_Roll/1 -> AutoPilot Inside Quatrocopter/1(u_roll)
  u_Pitch/1 -> AutoPilot Inside Quatrocopter/2(u_pitch)
  u_Yaw_rate/1 -> AutoPilot Inside Quatrocopter/4(u_yaw_rate)
  u_Thrust/1 -> AutoPilot Inside Quatrocopter/3(u_thrust)

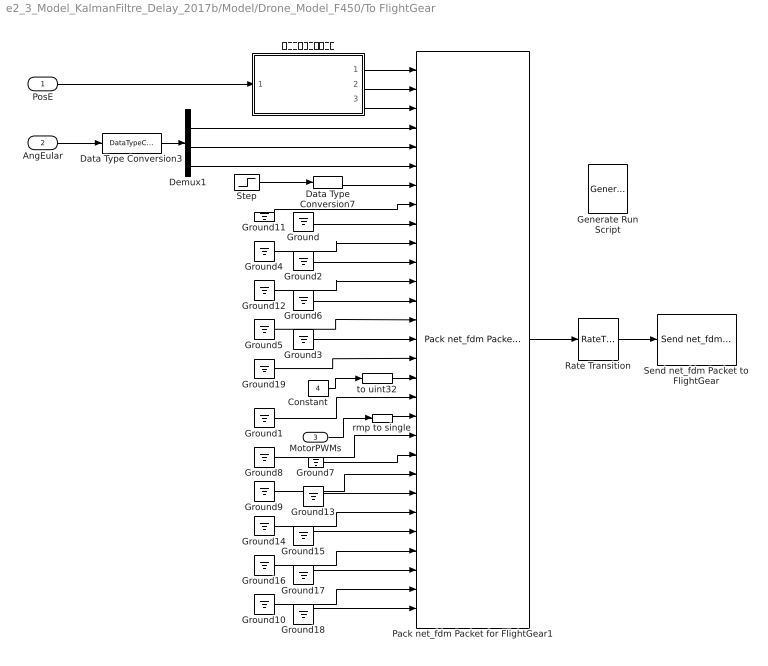
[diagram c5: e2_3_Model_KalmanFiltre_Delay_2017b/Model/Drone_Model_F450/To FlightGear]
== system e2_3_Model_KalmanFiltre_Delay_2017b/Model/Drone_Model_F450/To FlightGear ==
  PosE : Inport
  AngEular : Inport  Port=2
  MotorPWMs : Inport  Port=3
  Constant : Constant  Value=4
  Data Type Conversion3 : DataTypeConversion  OutDataTypeStr=single
  Data Type Conversion7 : DataTypeConversion  OutDataTypeStr=single
  Demux1 : Demux  Outputs=3
  Generate Run Script : aerolibfltsims/Generate Run Script  Architecture=Default  dataFlow=Send-Receive  GeometryModelName=Rotor4  AirportId=KSF0  RunwayId=10L  InitialAltitude=0  InitialHeading=0  OffsetDistance=0  OffsetAzimuth=0  OriginAddress=127.0.0.1  DestinationPort=5502  OriginPort=5505  LocalAddress=127.0.0.1  OutputFileName=runfg.bat  FlightGearBaseDirectory=C:\Program Files\FlightGear 2016.1.2
  Ground{,1..19} (20 alike) : Ground
  Pack net_fdm Packet for FlightGear1 : aerolibfltsims/Pack net_fdm Packet for FlightGear  FlightGearVersion=v2016.1  ShowPositionAttitudeInputs=on  ShowVelocityAccelerationInputs=off  ShowControlSurfacePositionInputs=on  ShowEngineFuelInputs=on  ShowLandingGearInputs=off  ShowEnvironmentInputs=off  SampleTime=0.01
  Rate Transition : RateTransition
  Send net_fdm Packet to FlightGear : aerolibfltsims/Send net_fdm Packet to FlightGear  DestinationIpAddress=127.0.0.1  DestinationPort=5502  LocalIpPort=-1  varLen=off  SampleTime=0.01
  Step : Step  Time=5  SampleTime=0
  rmp to single : DataTypeConversion  OutDataTypeStr=single
  to uint32 : DataTypeConversion  OutDataTypeStr=uint32
  三维位置转换成经纬度 : Subsystem
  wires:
  Pack net_fdm Packet for FlightGear1/1 -> Rate Transition/1
  Data Type Conversion7/1 -> Pack net_fdm Packet for FlightGear1/7
  Ground8/1 -> Pack net_fdm Packet for FlightGear1/20
  Ground/1 -> Pack net_fdm Packet for FlightGear1/9
  Ground7/1 -> Pack net_fdm Packet for FlightGear1/21
  Ground9/1 -> Pack net_fdm Packet for FlightGear1/22
  Ground13/1 -> Pack net_fdm Packet for FlightGear1/23
  Ground14/1 -> Pack net_fdm Packet for FlightGear1/24
  Ground15/1 -> Pack net_fdm Packet for FlightGear1/25
  Ground16/1 -> Pack net_fdm Packet for FlightGear1/26
  Ground17/1 -> Pack net_fdm Packet for FlightGear1/27
  Ground10/1 -> Pack net_fdm Packet for FlightGear1/28
  Ground18/1 -> Pack net_fdm Packet for FlightGear1/29
  Step/1 -> Data Type Conversion7/1
  to uint32/1 -> Pack net_fdm Packet for FlightGear1/17
  Ground1/1 -> Pack net_fdm Packet for FlightGear1/18
  Ground3/1 -> Pack net_fdm Packet for FlightGear1/15
  Ground5/1 -> Pack net_fdm Packet for FlightGear1/14
  Ground6/1 -> Pack net_fdm Packet for FlightGear1/13
  Ground4/1 -> Pack net_fdm Packet for FlightGear1/10
  Ground11/1 -> Pack net_fdm Packet for FlightGear1/8
  Demux1/3 -> Pack net_fdm Packet for FlightGear1/6
  Demux1/2 -> Pack net_fdm Packet for FlightGear1/5
  Demux1/1 -> Pack net_fdm Packet for FlightGear1/4
  Constant/1 -> to uint32/1
  rmp to single/1 -> Pack net_fdm Packet for FlightGear1/19
  Ground2/1 -> Pack net_fdm Packet for FlightGear1/11
  Ground12/1 -> Pack net_fdm Packet for FlightGear1/12
  Ground19/1 -> Pack net_fdm Packet for FlightGear1/16
  MotorPWMs/1 -> rmp to single/1
  Rate Transition/1 -> Send net_fdm Packet to FlightGear/1
  AngEular/1 -> Data Type Conversion3/1
  PosE/1 -> 三维位置转换成经纬度/1(pos_e)
  Data Type Conversion3/1 -> Demux1/1
  三维位置转换成经纬度/1(l) -> Pack net_fdm Packet for FlightGear1/1
  三维位置转换成经纬度/2(u) -> Pack net_fdm Packet for FlightGear1/2
  三维位置转换成经纬度/3(h) -> Pack net_fdm Packet for FlightGear1/3

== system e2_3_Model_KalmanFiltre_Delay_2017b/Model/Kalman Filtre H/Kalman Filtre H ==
  The system output: Position : Inport
  Demux : Demux  Outputs=3
  Kalman Filtre for getting the velocity H : MATLAB Function  TreatAsAtomicUnit=on  SystemSampleTime=0.01
  Memory block for resolving the 'algebraic loop' problem : Memory
  Scope2 : Scope
  Scope4 : Scope  NumInputPorts=2
  Out velocity feedback : Outport  VectorParamsAs1DForOutWhenUnconnected=off
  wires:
  Demux/2 -> Out velocity feedback/1
  Memory block for resolving the 'algebraic loop' problem/1 -> Demux/1
  Kalman Filtre for getting the velocity H/1(Covariance_matrice) -> Scope2/1
  The system output: Position/1 -> Kalman Filtre for getting the velocity H/1(Mesurement_Velocity)
  Demux/1 -> Scope4/1
  Kalman Filtre for getting the velocity H/2(X_Kalmanfiltred) -> Memory block for resolving the 'algebraic loop' problem/1
  Demux/3 -> Scope4/2

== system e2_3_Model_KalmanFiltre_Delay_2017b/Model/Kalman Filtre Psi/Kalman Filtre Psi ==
  The system output: Position : Inport
  Demux : Demux  Outputs=3
  Kalman Filtre for getting the velocity Psi : MATLAB Function  TreatAsAtomicUnit=on  SystemSampleTime=0.01
  Memory block for resolving the 'algebraic loop' problem : Memory
  Scope1 : Scope  NumInputPorts=2
  Scope2 : Scope
  Out velocity feedback : Outport  VectorParamsAs1DForOutWhenUnconnected=off
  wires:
  Demux/2 -> Out velocity feedback/1
  Kalman Filtre for getting the velocity Psi/1(Covariance_matrice) -> Scope2/1
  The system output: Position/1 -> Kalman Filtre for getting the velocity Psi/1(Mesurement_Velocity)
  Demux/1 -> Scope1/1
  Demux/3 -> Scope1/2
  Kalman Filtre for getting the velocity Psi/2(X_Kalmanfiltred) -> Memory block for resolving the 'algebraic loop' problem/1
  Memory block for resolving the 'algebraic loop' problem/1 -> Demux/1

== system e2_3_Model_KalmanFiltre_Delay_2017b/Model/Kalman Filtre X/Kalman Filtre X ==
  The system output: Position : Inport
  Demux : Demux  Outputs=3
  Kalman Filtre for getting the velocity X : MATLAB Function  TreatAsAtomicUnit=on  SystemSampleTime=0.01
  Memory block for resolving the 'algebraic loop' problem : Memory
  Scope2 : Scope
  Scope4 : Scope  NumInputPorts=2
  Out velocity feedback : Outport  VectorParamsAs1DForOutWhenUnconnected=off
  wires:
  Kalman Filtre for getting the velocity X/1(Covariance_matrice) -> Scope2/1
  Kalman Filtre for getting the velocity X/2(X_Kalmanfiltred) -> Memory block for resolving the 'algebraic loop' problem/1
  Memory block for resolving the 'algebraic loop' problem/1 -> Demux/1
  The system output: Position/1 -> Kalman Filtre for getting the velocity X/1(Mesurement_Velocity)
  Demux/2 -> Out velocity feedback/1
  Demux/1 -> Scope4/2
  Demux/3 -> Scope4/1

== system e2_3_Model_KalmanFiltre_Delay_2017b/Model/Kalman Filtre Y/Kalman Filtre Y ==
  The system output: Position : Inport
  Demux : Demux  Outputs=3
  Kalman Filtre for getting the velocity Y : MATLAB Function  TreatAsAtomicUnit=on  SystemSampleTime=0.01
  Memory block for resolving the 'algebraic loop' problem : Memory
  Scope2 : Scope
  Scope4 : Scope  NumInputPorts=2
  Out velocity feedback : Outport  VectorParamsAs1DForOutWhenUnconnected=off
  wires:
  Kalman Filtre for getting the velocity Y/2(X_Kalmanfiltred) -> Memory block for resolving the 'algebraic loop' problem/1
  Demux/2 -> Out velocity feedback/1
  Kalman Filtre for getting the velocity Y/1(Covariance_matrice) -> Scope2/1
  Memory block for resolving the 'algebraic loop' problem/1 -> Demux/1
  The system output: Position/1 -> Kalman Filtre for getting the velocity Y/1(Mesurement_Velocity)
  Demux/1 -> Scope4/1
  Demux/3 -> Scope4/2

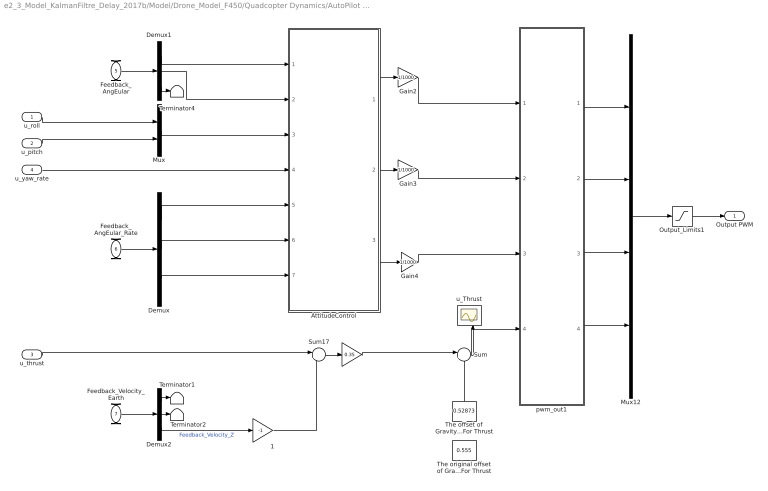
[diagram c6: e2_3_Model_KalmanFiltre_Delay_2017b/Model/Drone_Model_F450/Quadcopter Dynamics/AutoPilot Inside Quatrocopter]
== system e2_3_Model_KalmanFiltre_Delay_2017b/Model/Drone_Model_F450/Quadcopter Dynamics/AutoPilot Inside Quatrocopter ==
  u_roll : Inport
  u_pitch : Inport  Port=2
  u_thrust : Inport  Port=3
  u_yaw_rate : Inport  Port=4
  Feedback_AngEular : Inport  Port=5
  Feedback_AngEular_Rate : Inport  Port=6
  Feedback_Velocity_Earth : Inport  Port=7
  "          " : Gain  Gain=0.35
  "          1" : Gain  Gain=-1
  AttitudeControl : Subsystem
  Demux : Demux  Outputs=3
  Demux1 : Demux  Outputs=3
  Demux2 : Demux  Outputs=3
  Gain2 : Gain  Gain=1/1000
  Gain3 : Gain  Gain=1/1000
  Gain4 : Gain  Gain=1/1000
  Mux : Mux  Inputs=2
  Mux12 : Mux
  Output_Limits1 : Saturate  UpperLimit=2000  LowerLimit=1000
  Sum : Sum  Inputs=|++
  Sum17 : Sum  Inputs=|+-
  Terminator1 : Terminator
  Terminator2 : Terminator
  Terminator4 : Terminator
  The offset of Gravity&AirDrag For Thrust : Constant  Value=0.52873
  The original offset of Gravity&AirDrag For Thrust : Constant  Value=0.555
  pwm_out1 : MATLAB Function  TreatAsAtomicUnit=on  SystemSampleTime=0.01
  u_Thrust : Scope  NumInputPorts=2
  Output PWM : Outport  VectorParamsAs1DForOutWhenUnconnected=off
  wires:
  Mux12/1 -> Output_Limits1/1
  pwm_out1/1(M1) -> Mux12/1
  pwm_out1/3(M3) -> Mux12/3
  pwm_out1/2(M2) -> Mux12/2
  pwm_out1/4(M4) -> Mux12/4
  u_roll/1 -> Mux/1
  Demux/1 -> AttitudeControl/5(p)
  Demux1/2 -> AttitudeControl/2(theta)
  Feedback_AngEular/1 -> Demux1/1
  Feedback_AngEular_Rate/1 -> Demux/1
  Demux/3 -> AttitudeControl/7(r)
  Demux1/1 -> AttitudeControl/1(phi)
  Demux1/3 -> Terminator4/1
  Demux/2 -> AttitudeControl/6(q)
  u_yaw_rate/1 -> AttitudeControl/4(yaw)
  AttitudeControl/1(Roll) -> Gain2/1
  AttitudeControl/3(Yaw) -> Gain4/1
  AttitudeControl/2(Pitch) -> Gain3/1
  Gain2/1 -> pwm_out1/1(Roll)
  Gain4/1 -> pwm_out1/3(Yaw)
  Mux/1 -> AttitudeControl/3(roll_pitch)
  u_pitch/1 -> Mux/2
  Gain3/1 -> pwm_out1/2(Pitch)
  Output_Limits1/1 -> Output PWM/1
  Feedback_Velocity_Earth/1 -> Demux2/1
  Demux2/1 -> Terminator1/1
  Demux2/2 -> Terminator2/1
  Demux2/3 -> "          1"/1  "Feedback_Velocity_Z"
  Sum/1 -> pwm_out1/4(Thrust), u_Thrust/2
  Sum17/1 -> "          "/1
  "          1"/1 -> Sum17/2
  The offset of Gravity&AirDrag For Thrust/1 -> Sum/2
  "          "/1 -> Sum/1
  u_thrust/1 -> Sum17/1

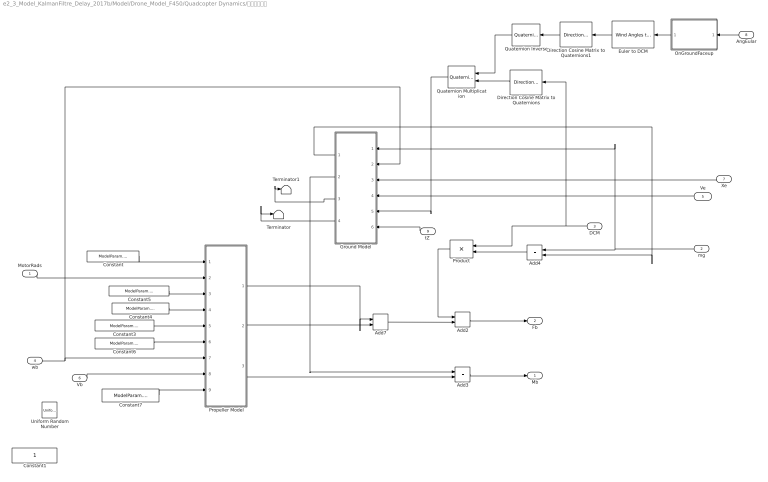
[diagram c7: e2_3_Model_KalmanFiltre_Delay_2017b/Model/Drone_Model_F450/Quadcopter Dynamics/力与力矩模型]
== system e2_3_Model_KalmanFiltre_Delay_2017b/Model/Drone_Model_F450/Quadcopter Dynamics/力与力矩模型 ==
  MotorRads : Inport
  mg : Inport  Port=2
  DCM : Inport  Port=3
  wb : Inport  Port=4
  Ve : Inport  Port=5
  Vb : Inport  Port=6
  Xe : Inport  Port=7
  AngEular : Inport  Port=8
  "tZ " : Inport  Port=9
  Add{2..4,7} (4 alike) : Sum
  Constant : Constant  Value=ModelParam.uavType
  Constant1 : Constant  Commented=on
  Constant3 : Constant  Value=ModelParam.rotorCt
  Constant4 : Constant  Value=ModelParam.rotorCm
  Constant5 : Constant  Value=ModelParam.uavR
  Constant6 : Constant  Value=ModelParam.motorJm
  Constant7 : Constant  Value=ModelParam.uavCd
  Direction Cosine Matrix to Quaternions : sharedtransform/Direction Cosine Matrix  to Quaternions
  Direction Cosine Matrix to Quaternions1 : sharedtransform/Direction Cosine Matrix  to Quaternions
  Euler to DCM : aerolibtransform2/Wind Angles to  Direction Cosine Matrix
  Ground Model : MATLAB Function  TreatAsAtomicUnit=on
  OnGroundFaceup : MATLAB Function  TreatAsAtomicUnit=on
  Product : Product  Multiplication=Matrix(*)
  Propeller Model : MATLAB Function  TreatAsAtomicUnit=on
  Quaternion Inverse : aerolibutil/Quaternion Inverse
  Quaternion Multiplication : aerolibutil/Quaternion Multiplication
  Terminator : Terminator
  Terminator1 : Terminator
  Uniform Random Number : UniformRandomNumber  Commented=on  Minimum=[-1,-1,-1]  Maximum=[1,1,1]  Seed=[145787,351545,2864]  SampleTime=0.05
  Mb : Outport  VectorParamsAs1DForOutWhenUnconnected=off
  Fb : Outport  Port=2  VectorParamsAs1DForOutWhenUnconnected=off
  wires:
  wb/1 -> Ground Model/2(wb), Propeller Model/7(wb)
  Ve/1 -> Ground Model/4(Ve)
  Xe/1 -> Ground Model/3(Xe)
  MotorRads/1 -> Propeller Model/2(w)
  Constant4/1 -> Propeller Model/4(Cm)
  Constant5/1 -> Propeller Model/3(R)
  Constant6/1 -> Propeller Model/6(Jm)
  Vb/1 -> Propeller Model/8(Vb)
  Constant7/1 -> Propeller Model/9(Cd)
  DCM/1 -> Product/1, Direction Cosine Matrix to Quaternions/1
  Ground Model/2(M1) -> Add3/1
  Propeller Model/3(Mb) -> Add3/2
  mg/1 -> Ground Model/1(mg), Add4/1
  Add4/1 -> Product/2
  Ground Model/1(F1) -> Add4/2
  Product/1 -> Add2/1
  Propeller Model/1(Fb) -> Add7/1
  Add7/1 -> Add2/2
  Propeller Model/2(Fd) -> Add7/2
  Constant3/1 -> Propeller Model/5(Ct)
  Direction Cosine Matrix to Quaternions/1 -> Quaternion Multiplication/2
  AngEular/1 -> OnGroundFaceup/1(EulerAng)
  OnGroundFaceup/1(y) -> Euler to DCM/1
  Euler to DCM/1 -> Direction Cosine Matrix to Quaternions1/1
  Direction Cosine Matrix to Quaternions1/1 -> Quaternion Inverse/1
  Quaternion Inverse/1 -> Quaternion Multiplication/1
  Quaternion Multiplication/1 -> Ground Model/5(Quet)
  Constant/1 -> Propeller Model/1(uavType)
  Add2/1 -> Fb/1
  Add3/1 -> Mb/1
  "tZ "/1 -> Ground Model/6(terrainZ)
  Ground Model/4(takeoff) -> Terminator/1
  Ground Model/3(landed) -> Terminator1/1

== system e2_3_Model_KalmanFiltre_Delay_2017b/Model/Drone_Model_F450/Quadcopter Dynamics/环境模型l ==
  Xe : Inport
  Vb : Inport  Port=2
  Constant16 : Constant  Value=ModelParam.envAltitude
  Flat Earth to LLA : aerolibtransform2/Flat Earth to LLA  units=Metric (MKS)  ptype=Earth (WGS84)  F=1/298.257223563  R=6378137  LL0=[ModelParam.envLatitude ModelParam.envLongitude]  psi=0
  ISA Atmosphere Model : aerolibatmos2/ISA Atmosphere Model  custom=off  g=9.80665  gamma=1.4  R=287.0531  L=0.0065  h_trop=11000  h_strat=20000  rho0=1.225  P0=101325  T0=288.15  h0=0
  Mux : Mux  Inputs=2
  Reshape : Reshape
  Saturation : Saturate  UpperLimit=100000  LowerLimit=0
  Temperature Conversion : aerolibconvert2/Temperature Conversion  IU=K  OU=C
  Terminator3 : Terminator
  "WGS84 Gravity Model " : aerolibobsolete/WGS84 Gravity Model   model=WGS84 Taylor Series  units=Metric (MKS)  no_atmos=on  precessing=on  jd_loc=off  month=October  day=10  year=2004  no_centrifugal=on  action=Warning
  gravity : Outport  VectorParamsAs1DForOutWhenUnconnected=off
  Windb : Outport  Port=2  VectorParamsAs1DForOutWhenUnconnected=off
  Rho : Outport  Port=3  VectorParamsAs1DForOutWhenUnconnected=off
  TempC : Outport  Port=4  VectorParamsAs1DForOutWhenUnconnected=off
  AirPressure : Outport  Port=5  VectorParamsAs1DForOutWhenUnconnected=off
  PosGPS : Outport  Port=6  VectorParamsAs1DForOutWhenUnconnected=off
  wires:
  "WGS84 Gravity Model "/1 -> Reshape/1
  Reshape/1 -> gravity/1
  ISA Atmosphere Model/1 -> Temperature Conversion/1
  ISA Atmosphere Model/2 -> Terminator3/1
  ISA Atmosphere Model/3 -> AirPressure/1
  ISA Atmosphere Model/4 -> Rho/1
  Temperature Conversion/1 -> TempC/1
  Flat Earth to LLA/2 -> Saturation/1
  Saturation/1 -> Mux/2, ISA Atmosphere Model/1
  Constant16/1 -> Flat Earth to LLA/2
  Mux/1 -> PosGPS/1, "WGS84 Gravity Model "/1
  Xe/1 -> Flat Earth to LLA/1
  Flat Earth to LLA/1 -> Mux/1
  Vb/1 -> Windb/1

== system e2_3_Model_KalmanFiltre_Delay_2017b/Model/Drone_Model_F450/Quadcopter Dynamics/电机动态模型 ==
  inPWMs : Inport
  Demux : Demux
  Motor_Dynamics_1 : StateSpace  A=-1/ModelParam.motorT  C=1/ModelParam.motorT  D=0  InitialCondition=ModelInit.RPM(1)*ModelParam.motorT
  Motor_Dynamics_2 : StateSpace  A=-1/ModelParam.motorT  C=1/ModelParam.motorT  D=0  InitialCondition=ModelInit.RPM(2)*ModelParam.motorT
  Motor_Dynamics_3 : StateSpace  A=-1/ModelParam.motorT  C=1/ModelParam.motorT  D=0  InitialCondition=ModelInit.RPM(3)*ModelParam.motorT
  Motor_Dynamics_4 : StateSpace  A=-1/ModelParam.motorT  C=1/ModelParam.motorT  D=0  InitialCondition=ModelInit.RPM(4)*ModelParam.motorT
  Mux : Mux
  Signal_Saturation_{1..4} (4 alike) : Saturate  UpperLimit=1  LowerLimit=0
  Throttle To RPM Gain and Cutoff_1 : Subsystem
  Throttle To RPM Gain and Cutoff_2 : Subsystem
  Throttle To RPM Gain and Cutoff_3 : Subsystem
  Throttle To RPM Gain and Cutoff_4 : Subsystem
  MotorRads : Outport  VectorParamsAs1DForOutWhenUnconnected=off
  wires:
  Demux/1 -> Signal_Saturation_1/1
  Demux/2 -> Signal_Saturation_2/1
  Demux/3 -> Signal_Saturation_3/1
  Demux/4 -> Signal_Saturation_4/1
  inPWMs/1 -> Demux/1
  Throttle To RPM Gain and Cutoff_1/1(Out5) -> Motor_Dynamics_1/1
  Throttle To RPM Gain and Cutoff_2/1(Out5) -> Motor_Dynamics_2/1
  Throttle To RPM Gain and Cutoff_3/1(Out5) -> Motor_Dynamics_3/1
  Throttle To RPM Gain and Cutoff_4/1(Out5) -> Motor_Dynamics_4/1
  Mux/1 -> MotorRads/1
  Signal_Saturation_1/1 -> Throttle To RPM Gain and Cutoff_1/1(In5)
  Signal_Saturation_2/1 -> Throttle To RPM Gain and Cutoff_2/1(In5)
  Signal_Saturation_3/1 -> Throttle To RPM Gain and Cutoff_3/1(In5)
  Signal_Saturation_4/1 -> Throttle To RPM Gain and Cutoff_4/1(In5)
  Motor_Dynamics_1/1 -> Mux/1
  Motor_Dynamics_2/1 -> Mux/2
  Motor_Dynamics_3/1 -> Mux/3
  Motor_Dynamics_4/1 -> Mux/4
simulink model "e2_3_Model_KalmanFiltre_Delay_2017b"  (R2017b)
settings: Solver=ode4  StartTime=0.0  StopTime=100  FixedStep=sampleTime  RelTol=1e-3  EnableMultiTasking=on
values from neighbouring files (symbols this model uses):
  k_d_x = 0.7    [startSimulation.m]
  k_d_y = 0.7    [startSimulation.m]
  k_d_yaw = 0.05    [startSimulation.m]
  k_d_z = 0.05    [startSimulation.m]
  k_i_x = 0.01    [startSimulation.m]
  k_i_y = 0.01    [startSimulation.m]
  k_i_yaw = 0.01    [startSimulation.m]
  k_i_z = 0.01    [startSimulation.m]
  k_p_x = 1    [startSimulation.m]
  k_p_y = 1    [startSimulation.m]
  k_p_yaw = 2    [startSimulation.m]
  k_p_z = 3    [startSimulation.m]
  Kd_RP_AgngleRate = 0.005    [startSimulation.m]
  Kd_YAW_AngleRate = 0.05    [startSimulation.m]
  Ki_RP_AgngleRate = 0.01    [startSimulation.m]
  Ki_YAW_AngleRate = 0.8    [startSimulation.m]
  Kp_RP_AgngleRate = 0.55    [startSimulation.m]
  Kp_RP_ANGLE = 6.5    [startSimulation.m]
  Kp_YAW_AngleRate = 3.2    [startSimulation.m]
  saturation_psi = 2    [startSimulation.m]
  saturation_x = 2    [startSimulation.m]
  saturation_y = 2    [startSimulation.m]
  saturation_z = 2    [startSimulation.m]
  simDT = 0.01    [startSimulation.m]
undefined symbols (not defined in the file or in its folder): DiscIntNeverNeededParam, Earth, earthRadius, KiPitchAttitude, KiRollAttitude, ModelInit, ModelParam, Receive, Send, sigbuilder_block, unidrnd, WGS84
libraries: simulink x26, sharedtransform x3, aerolibtransform2 x3, aerolibfltsims x3, aerolibutil x2, aerolibanimutils x1, shared6dof x1, aerolibatmos2 x1, aerolibconvert2 x1, aerolibobsolete x1, aerolibasang x1, aerolibnav x1
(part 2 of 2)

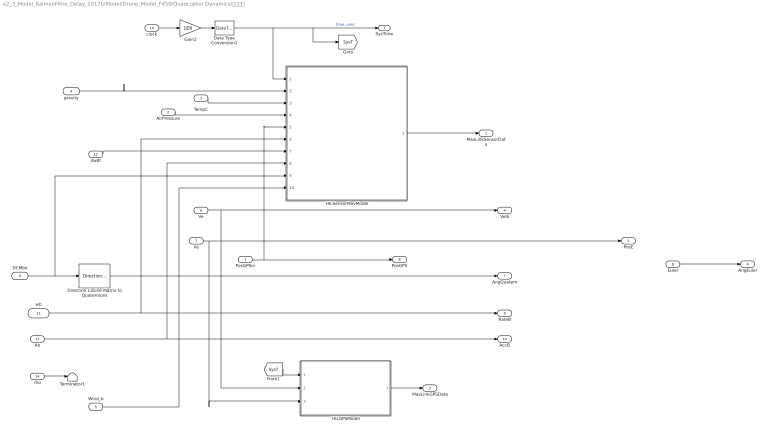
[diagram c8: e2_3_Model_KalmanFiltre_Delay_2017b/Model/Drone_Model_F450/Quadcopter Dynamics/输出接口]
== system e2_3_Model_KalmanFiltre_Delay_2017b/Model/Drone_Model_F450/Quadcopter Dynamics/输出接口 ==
  PosGPSin : Inport
  AirPressure : Inport  Port=2
  TempC : Inport  Port=3
  gravity : Inport  Port=4
  Wind_b : Inport  Port=5
  Ve : Inport  Port=6
  Xe : Inport  Port=7
  Euler : Inport  Port=8
  DCMbe : Inport  Port=9
  clock : Inport  Port=10
  wb : Inport  Port=11
  dwdt : Inport  Port=12
  Ab : Inport  Port=13
  rho : Inport  Port=14
  Data Type Conversion1 : DataTypeConversion  OutDataTypeStr=uint32
  Direction Cosine Matrix to Quaternions : sharedtransform/Direction Cosine Matrix  to Quaternions
  Gain2 : Gain  Gain=1E6
  HILGPSModel : Subsystem
  HILSensorMavModel : Subsystem
  Terminator1 : Terminator
  MavLinkSensorData : Outport  VectorParamsAs1DForOutWhenUnconnected=off
  MavLinkGPSData : Outport  Port=2  VectorParamsAs1DForOutWhenUnconnected=off
  SysTime : Outport  Port=3  VectorParamsAs1DForOutWhenUnconnected=off
  VelE : Outport  Port=4  VectorParamsAs1DForOutWhenUnconnected=off
  PosE : Outport  Port=5  VectorParamsAs1DForOutWhenUnconnected=off
  AngEuler : Outport  Port=6  VectorParamsAs1DForOutWhenUnconnected=off
  AngQuatern : Outport  Port=7  VectorParamsAs1DForOutWhenUnconnected=off
  PosGPS : Outport  Port=8  VectorParamsAs1DForOutWhenUnconnected=off
  RateB : Outport  Port=9  VectorParamsAs1DForOutWhenUnconnected=off
  AccB : Outport  Port=10  VectorParamsAs1DForOutWhenUnconnected=off
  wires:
  HILGPSModel/1(MavLinkGPS) -> MavLinkGPSData/1
  Gain2/1 -> Data Type Conversion1/1
  Data Type Conversion1/1 -> [SysT], SysTime/1, HILSensorMavModel/1(time_usec)  "time_usec"
  clock/1 -> Gain2/1
  PosGPSin/1 -> HILSensorMavModel/5(GPSPos), PosGPS/1
  Euler/1 -> AngEuler/1
  Direction Cosine Matrix to Quaternions/1 -> AngQuatern/1
  TempC/1 -> HILSensorMavModel/3(TempC)
  AirPressure/1 -> HILSensorMavModel/4(pressure)
  dwdt/1 -> HILSensorMavModel/7(dwt)
  HILSensorMavModel/1(SensorOut) -> MavLinkSensorData/1
  Ab/1 -> AccB/1, HILSensorMavModel/8(Ab)
  Ve/1 -> VelE/1, HILGPSModel/2(Ve)
  DCMbe/1 -> Direction Cosine Matrix to Quaternions/1, HILSensorMavModel/9(DCMbe)
  gravity/1 -> HILSensorMavModel/2(Gravity)
  Xe/1 -> PosE/1, HILGPSModel/3(Xe)
  wb/1 -> HILSensorMavModel/6(wb), RateB/1
  [SysT] -> HILGPSModel/1(time_usec)
  Wind_b/1 -> HILSensorMavModel/10(windB)
  rho/1 -> Terminator1/1

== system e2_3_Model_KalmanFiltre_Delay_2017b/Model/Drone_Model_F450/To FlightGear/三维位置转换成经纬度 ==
  pos_e : Inport
  Constant1 : Constant  Value=5  VectorParams1D=off
  Constant2 : Constant  Value=-2.1361  VectorParams1D=off
  Constant3 : Constant  Value=0.65673  VectorParams1D=off
  Demux : Demux  Outputs=3
  Gain1 : Gain  Gain=10/earthRadius
  Gain2 : Gain  Gain=10/earthRadius
  Gain4 : Gain  Gain=-1
  Gain8 : Gain  Gain=-10
  Sum10 : Sum  Inputs=|++
  Sum8 : Sum  Inputs=|++
  Sum9 : Sum  Inputs=|++
  l : Outport  VectorParamsAs1DForOutWhenUnconnected=off
  u : Outport  Port=2  VectorParamsAs1DForOutWhenUnconnected=off
  h : Outport  Port=3  VectorParamsAs1DForOutWhenUnconnected=off
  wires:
  Sum10/1 -> h/1
  Sum9/1 -> u/1
  Sum8/1 -> l/1
  Demux/1 -> Gain4/1
  Demux/2 -> Gain1/1
  Demux/3 -> Gain8/1
  Gain1/1 -> Sum8/1
  Constant1/1 -> Sum10/2
  Constant3/1 -> Sum9/2
  Constant2/1 -> Sum8/2
  Gain8/1 -> Sum10/1
  Gain2/1 -> Sum9/1
  Gain4/1 -> Gain2/1
  pos_e/1 -> Demux/1

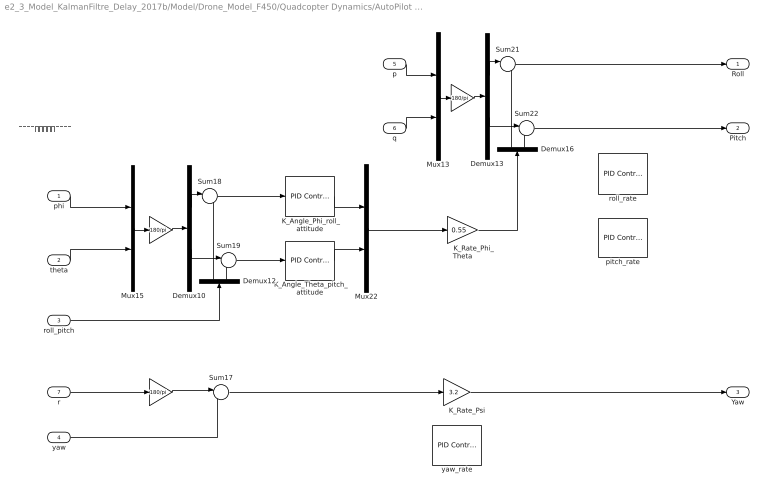
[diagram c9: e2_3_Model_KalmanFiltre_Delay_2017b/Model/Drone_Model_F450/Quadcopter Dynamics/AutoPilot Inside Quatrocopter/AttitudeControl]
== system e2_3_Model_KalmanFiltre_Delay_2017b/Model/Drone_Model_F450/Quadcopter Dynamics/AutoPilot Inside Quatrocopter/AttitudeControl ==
  note: 期望都是度，反馈的都是弧度
  phi : Inport
  theta : Inport  Port=2
  roll_pitch : Inport  Port=3
  yaw : Inport  Port=4
  p : Inport  Port=5
  q : Inport  Port=6
  r : Inport  Port=7
  " " : Gain  Gain=180/pi
  "  " : Gain  Gain=180/pi
  "          " : Gain  Gain=180/pi
  "          K_Rate_Phi_Theta" : Gain  Gain=0.55
  "         K_Rate_Psi" : Gain  Gain=3.2
  " K_Angle_Phi_roll_attitude" : simulink/Continuous/PID Controller  Controller=P  Form=Parallel  TimeDomain=Discrete-time  SampleTime=-1  IntegratorMethod=Forward Euler  FilterMethod=Forward Euler  ControllerParametersSource=internal  P=Kp_RP_ANGLE  I=KiRollAttitude  D=0.01  UseFilter=on  N=100  TunerSelectOption=Transfer Function Based (PID Tuner App)  InitialConditionSource=internal  InitialConditionForIntegrator=0  InitialConditionForFilter=0  DifferentiatorICPrevScaledInput=0  ExternalReset=none  TrackingMode=off  Kt=1  LimitOutput=on  UpperSaturationLimit=180  LowerSaturationLimit=-180  LinearizeAsGain=on  AntiWindupMode=back-calculation  Kb=1  POutMin=[]  POutMax=[]  IOutMin=[]  IOutMax=[]  DOutMin=[]  DOutMax=[]  NOutMin=[]  NOutMax=[]  SumOutMin=[]  SumOutMax=[]  SaturationOutMin=[]  SaturationOutMax=[]  PParamMin=[]  PParamMax=[]  IParamMin=[]  IParamMax=[]  DParamMin=[]  DParamMax=[]  NParamMin=[]  NParamMax=[]  KbParamMin=[]  KbParamMax=[]  KtParamMin=[]  KtParamMax=[]  KbOutMin=[]  KbOutMax=[]  KtOutMin=[]  KtOutMax=[]  IntegratorOutMin=[]  IntegratorOutMax=[]  FilterOutMin=[]  FilterOutMax=[]  SumI1OutMin=[]  SumI1OutMax=[]  SumI2OutMin=[]  SumI2OutMax=[]  SumI3OutMin=[]  SumI3OutMax=[]  SumDOutMin=[]  SumDOutMax=[]  DifferentiatorOutMin=[]  DifferentiatorOutMax=[]  FilterDiffOutCoefMin=[]  FilterDiffOutCoefMax=[]  ReciprocalOutMin=[]  ReciprocalOutMax=[]  SumDenOutMin=[]  SumDenOutMax=[]  SumNumOutMin=[]  SumNumOutMax=[]  DivideOutMin=[]  DivideOutMax=[]  IntegratorContinuousStateAttributes=''  IntegratorStateMustResolveToSignalObject=off  IntegratorRTWStateStorageClass=Auto  FilterContinuousStateAttributes=''  FilterStateMustResolveToSignalObject=off  FilterRTWStateStorageClass=Auto  InitialConditionSetting=State (most efficient)
  " K_Angle_Theta_pitch_attitude" : simulink/Continuous/PID Controller  Controller=P  Form=Parallel  TimeDomain=Discrete-time  SampleTime=-1  IntegratorMethod=Forward Euler  FilterMethod=Forward Euler  ControllerParametersSource=internal  P=Kp_RP_ANGLE  I=KiPitchAttitude  D=0.01  UseFilter=on  N=100  TunerSelectOption=Transfer Function Based (PID Tuner App)  InitialConditionSource=internal  InitialConditionForIntegrator=0  InitialConditionForFilter=0  DifferentiatorICPrevScaledInput=0  ExternalReset=none  TrackingMode=off  Kt=1  LimitOutput=on  UpperSaturationLimit=180  LowerSaturationLimit=-180  LinearizeAsGain=on  AntiWindupMode=back-calculation  Kb=1  POutMin=[]  POutMax=[]  IOutMin=[]  IOutMax=[]  DOutMin=[]  DOutMax=[]  NOutMin=[]  NOutMax=[]  SumOutMin=[]  SumOutMax=[]  SaturationOutMin=[]  SaturationOutMax=[]  PParamMin=[]  PParamMax=[]  IParamMin=[]  IParamMax=[]  DParamMin=[]  DParamMax=[]  NParamMin=[]  NParamMax=[]  KbParamMin=[]  KbParamMax=[]  KtParamMin=[]  KtParamMax=[]  KbOutMin=[]  KbOutMax=[]  KtOutMin=[]  KtOutMax=[]  IntegratorOutMin=[]  IntegratorOutMax=[]  FilterOutMin=[]  FilterOutMax=[]  SumI1OutMin=[]  SumI1OutMax=[]  SumI2OutMin=[]  SumI2OutMax=[]  SumI3OutMin=[]  SumI3OutMax=[]  SumDOutMin=[]  SumDOutMax=[]  DifferentiatorOutMin=[]  DifferentiatorOutMax=[]  FilterDiffOutCoefMin=[]  FilterDiffOutCoefMax=[]  ReciprocalOutMin=[]  ReciprocalOutMax=[]  SumDenOutMin=[]  SumDenOutMax=[]  SumNumOutMin=[]  SumNumOutMax=[]  DivideOutMin=[]  DivideOutMax=[]  IntegratorContinuousStateAttributes=''  IntegratorStateMustResolveToSignalObject=off  IntegratorRTWStateStorageClass=Auto  FilterContinuousStateAttributes=''  FilterStateMustResolveToSignalObject=off  FilterRTWStateStorageClass=Auto  InitialConditionSetting=State (most efficient)
  Demux{10,12..13,16} (4 alike) : Demux  Outputs=2
  Mux13 : Mux  Inputs=2
  Mux15 : Mux  Inputs=2
  Mux22 : Mux  Inputs=2
  Sum{17..19,21..22} (5 alike) : Sum  Inputs=|-+
  pitch_rate : simulink/Continuous/PID Controller  Controller=PID  Form=Parallel  TimeDomain=Discrete-time  SampleTime=-1  IntegratorMethod=Forward Euler  FilterMethod=Forward Euler  ControllerParametersSource=internal  P=Kp_RP_AgngleRate  I=Ki_RP_AgngleRate  D=Kd_RP_AgngleRate  UseFilter=off  N=100  TunerSelectOption=Transfer Function Based (PID Tuner App)  InitialConditionSource=internal  InitialConditionForIntegrator=0  InitialConditionForFilter=0  DifferentiatorICPrevScaledInput=0  ExternalReset=none  TrackingMode=off  Kt=1  LimitOutput=on  UpperSaturationLimit=500  LowerSaturationLimit=-500  LinearizeAsGain=on  AntiWindupMode=back-calculation  Kb=1  POutMin=[]  POutMax=[]  IOutMin=[]  IOutMax=[]  DOutMin=[]  DOutMax=[]  NOutMin=[]  NOutMax=[]  SumOutMin=[]  SumOutMax=[]  SaturationOutMin=[]  SaturationOutMax=[]  PParamMin=[]  PParamMax=[]  IParamMin=[]  IParamMax=[]  DParamMin=[]  DParamMax=[]  NParamMin=[]  NParamMax=[]  KbParamMin=[]  KbParamMax=[]  KtParamMin=[]  KtParamMax=[]  KbOutMin=[]  KbOutMax=[]  KtOutMin=[]  KtOutMax=[]  IntegratorOutMin=[]  IntegratorOutMax=[]  FilterOutMin=[]  FilterOutMax=[]  SumI1OutMin=[]  SumI1OutMax=[]  SumI2OutMin=[]  SumI2OutMax=[]  SumI3OutMin=[]  SumI3OutMax=[]  SumDOutMin=[]  SumDOutMax=[]  DifferentiatorOutMin=[]  DifferentiatorOutMax=[]  FilterDiffOutCoefMin=[]  FilterDiffOutCoefMax=[]  ReciprocalOutMin=[]  ReciprocalOutMax=[]  SumDenOutMin=[]  SumDenOutMax=[]  SumNumOutMin=[]  SumNumOutMax=[]  DivideOutMin=[]  DivideOutMax=[]  IntegratorContinuousStateAttributes=''  IntegratorStateMustResolveToSignalObject=off  IntegratorRTWStateStorageClass=Auto  FilterContinuousStateAttributes=''  FilterStateMustResolveToSignalObject=off  FilterRTWStateStorageClass=Auto  InitialConditionSetting=State (most efficient)
  roll_rate : simulink/Continuous/PID Controller  Controller=PID  Form=Parallel  TimeDomain=Discrete-time  SampleTime=-1  IntegratorMethod=Forward Euler  FilterMethod=Forward Euler  ControllerParametersSource=internal  P=Kp_RP_AgngleRate  I=Ki_RP_AgngleRate  D=Kd_RP_AgngleRate  UseFilter=off  N=100  TunerSelectOption=Transfer Function Based (PID Tuner App)  InitialConditionSource=internal  InitialConditionForIntegrator=0  InitialConditionForFilter=0  DifferentiatorICPrevScaledInput=0  ExternalReset=none  TrackingMode=off  Kt=1  LimitOutput=on  UpperSaturationLimit=500  LowerSaturationLimit=-500  LinearizeAsGain=on  AntiWindupMode=back-calculation  Kb=1  POutMin=[]  POutMax=[]  IOutMin=[]  IOutMax=[]  DOutMin=[]  DOutMax=[]  NOutMin=[]  NOutMax=[]  SumOutMin=[]  SumOutMax=[]  SaturationOutMin=[]  SaturationOutMax=[]  PParamMin=[]  PParamMax=[]  IParamMin=[]  IParamMax=[]  DParamMin=[]  DParamMax=[]  NParamMin=[]  NParamMax=[]  KbParamMin=[]  KbParamMax=[]  KtParamMin=[]  KtParamMax=[]  KbOutMin=[]  KbOutMax=[]  KtOutMin=[]  KtOutMax=[]  IntegratorOutMin=[]  IntegratorOutMax=[]  FilterOutMin=[]  FilterOutMax=[]  SumI1OutMin=[]  SumI1OutMax=[]  SumI2OutMin=[]  SumI2OutMax=[]  SumI3OutMin=[]  SumI3OutMax=[]  SumDOutMin=[]  SumDOutMax=[]  DifferentiatorOutMin=[]  DifferentiatorOutMax=[]  FilterDiffOutCoefMin=[]  FilterDiffOutCoefMax=[]  ReciprocalOutMin=[]  ReciprocalOutMax=[]  SumDenOutMin=[]  SumDenOutMax=[]  SumNumOutMin=[]  SumNumOutMax=[]  DivideOutMin=[]  DivideOutMax=[]  IntegratorContinuousStateAttributes=''  IntegratorStateMustResolveToSignalObject=off  IntegratorRTWStateStorageClass=Auto  FilterContinuousStateAttributes=''  FilterStateMustResolveToSignalObject=off  FilterRTWStateStorageClass=Auto  InitialConditionSetting=State (most efficient)
  yaw_rate : simulink/Continuous/PID Controller  Controller=PID  Form=Parallel  TimeDomain=Discrete-time  SampleTime=-1  IntegratorMethod=Forward Euler  FilterMethod=Forward Euler  ControllerParametersSource=internal  P=Kp_YAW_AngleRate  I=Ki_YAW_AngleRate  D=Kd_YAW_AngleRate  UseFilter=off  N=100  TunerSelectOption=Transfer Function Based (PID Tuner App)  InitialConditionSource=internal  InitialConditionForIntegrator=0  InitialConditionForFilter=0  DifferentiatorICPrevScaledInput=0  ExternalReset=none  TrackingMode=off  Kt=1  LimitOutput=on  UpperSaturationLimit=500  LowerSaturationLimit=-500  LinearizeAsGain=on  AntiWindupMode=back-calculation  Kb=1  POutMin=[]  POutMax=[]  IOutMin=[]  IOutMax=[]  DOutMin=[]  DOutMax=[]  NOutMin=[]  NOutMax=[]  SumOutMin=[]  SumOutMax=[]  SaturationOutMin=[]  SaturationOutMax=[]  PParamMin=[]  PParamMax=[]  IParamMin=[]  IParamMax=[]  DParamMin=[]  DParamMax=[]  NParamMin=[]  NParamMax=[]  KbParamMin=[]  KbParamMax=[]  KtParamMin=[]  KtParamMax=[]  KbOutMin=[]  KbOutMax=[]  KtOutMin=[]  KtOutMax=[]  IntegratorOutMin=[]  IntegratorOutMax=[]  FilterOutMin=[]  FilterOutMax=[]  SumI1OutMin=[]  SumI1OutMax=[]  SumI2OutMin=[]  SumI2OutMax=[]  SumI3OutMin=[]  SumI3OutMax=[]  SumDOutMin=[]  SumDOutMax=[]  DifferentiatorOutMin=[]  DifferentiatorOutMax=[]  FilterDiffOutCoefMin=[]  FilterDiffOutCoefMax=[]  ReciprocalOutMin=[]  ReciprocalOutMax=[]  SumDenOutMin=[]  SumDenOutMax=[]  SumNumOutMin=[]  SumNumOutMax=[]  DivideOutMin=[]  DivideOutMax=[]  IntegratorContinuousStateAttributes=''  IntegratorStateMustResolveToSignalObject=off  IntegratorRTWStateStorageClass=Auto  FilterContinuousStateAttributes=''  FilterStateMustResolveToSignalObject=off  FilterRTWStateStorageClass=Auto  InitialConditionSetting=State (most efficient)
  Roll : Outport  VectorParamsAs1DForOutWhenUnconnected=off
  Pitch : Outport  Port=2  VectorParamsAs1DForOutWhenUnconnected=off
  Yaw : Outport  Port=3  VectorParamsAs1DForOutWhenUnconnected=off
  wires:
  r/1 -> "          "/1
  q/1 -> Mux13/2
  phi/1 -> Mux15/1
  theta/1 -> Mux15/2
  "          "/1 -> Sum17/1
  Sum19/1 -> " K_Angle_Theta_pitch_attitude"/1
  Sum18/1 -> " K_Angle_Phi_roll_attitude"/1
  Demux16/1 -> Sum21/2
  yaw/1 -> Sum17/2
  roll_pitch/1 -> Demux12/1
  Demux16/2 -> Sum22/2
  Demux12/1 -> Sum18/2
  Demux12/2 -> Sum19/2
  p/1 -> Mux13/1
  Demux10/1 -> Sum18/1
  Demux10/2 -> Sum19/1
  Demux13/1 -> Sum21/1
  Demux13/2 -> Sum22/1
  Sum17/1 -> "         K_Rate_Psi"/1
  "         K_Rate_Psi"/1 -> Yaw/1
  Mux15/1 -> " "/1
  " K_Angle_Theta_pitch_attitude"/1 -> Mux22/2
  " K_Angle_Phi_roll_attitude"/1 -> Mux22/1
  Mux13/1 -> "  "/1
  "  "/1 -> Demux13/1
  " "/1 -> Demux10/1
  Mux22/1 -> "          K_Rate_Phi_Theta"/1
  Sum21/1 -> Roll/1
  Sum22/1 -> Pitch/1
  "          K_Rate_Phi_Theta"/1 -> Demux16/1

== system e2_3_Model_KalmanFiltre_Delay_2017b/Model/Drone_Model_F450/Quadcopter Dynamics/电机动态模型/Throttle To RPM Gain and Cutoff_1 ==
  note: Output equals linearly scaled RPM for given throttle input if throttle input >=Throttle Cuttoff (minThr) else output is zero.
  In5 : Inport
  Constant : Constant  Value=ModelParam.motorWb
  Gain : Gain  Gain=ModelParam.motorCr
  Minimum Throttle Cutoff : simulink/Logic and Bit Operations/Compare To Constant  relop=>=  const=ModelParam.motorMinThr  OutDataTypeStr=uint8
  Product : Product
  Sum1 : Sum  Inputs=++|
  Out5 : Outport  VectorParamsAs1DForOutWhenUnconnected=off
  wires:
  Minimum Throttle Cutoff/1 -> Product/2
  Product/1 -> Out5/1
  In5/1 -> Minimum Throttle Cutoff/1, Gain/1
  Gain/1 -> Sum1/2
  Sum1/1 -> Product/1
  Constant/1 -> Sum1/1

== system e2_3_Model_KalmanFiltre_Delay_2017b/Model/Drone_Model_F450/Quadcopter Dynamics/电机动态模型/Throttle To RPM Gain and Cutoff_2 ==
  note: Output equals linearly scaled RPM for given throttle input if throttle input >=Throttle Cuttoff (minThr) else output is zero.
  In5 : Inport
  Constant : Constant  Value=ModelParam.motorWb
  Gain : Gain  Gain=ModelParam.motorCr
  Minimum Throttle Cutoff : simulink/Logic and Bit Operations/Compare To Constant  relop=>=  const=ModelParam.motorMinThr  OutDataTypeStr=uint8
  Product : Product
  Sum1 : Sum  Inputs=++|
  Out5 : Outport  VectorParamsAs1DForOutWhenUnconnected=off
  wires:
  Minimum Throttle Cutoff/1 -> Product/2
  Product/1 -> Out5/1
  In5/1 -> Minimum Throttle Cutoff/1, Gain/1
  Gain/1 -> Sum1/2
  Sum1/1 -> Product/1
  Constant/1 -> Sum1/1

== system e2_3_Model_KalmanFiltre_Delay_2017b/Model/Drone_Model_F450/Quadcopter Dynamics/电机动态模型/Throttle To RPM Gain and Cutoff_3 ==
  note: Output equals linearly scaled RPM for given throttle input if throttle input >=Throttle Cuttoff (minThr) else output is zero.
  In5 : Inport
  Constant : Constant  Value=ModelParam.motorWb
  Gain : Gain  Gain=ModelParam.motorCr
  Minimum Throttle Cutoff : simulink/Logic and Bit Operations/Compare To Constant  relop=>=  const=ModelParam.motorMinThr  OutDataTypeStr=uint8
  Product : Product
  Sum1 : Sum  Inputs=++|
  Out5 : Outport  VectorParamsAs1DForOutWhenUnconnected=off
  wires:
  Minimum Throttle Cutoff/1 -> Product/2
  Product/1 -> Out5/1
  In5/1 -> Minimum Throttle Cutoff/1, Gain/1
  Gain/1 -> Sum1/2
  Sum1/1 -> Product/1
  Constant/1 -> Sum1/1

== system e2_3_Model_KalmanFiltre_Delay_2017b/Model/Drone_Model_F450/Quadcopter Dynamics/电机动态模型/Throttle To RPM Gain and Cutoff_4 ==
  note: Output equals linearly scaled RPM for given throttle input if throttle input >=Throttle Cuttoff (minThr) else output is zero.
  In5 : Inport
  Constant : Constant  Value=ModelParam.motorWb
  Gain : Gain  Gain=ModelParam.motorCr
  Minimum Throttle Cutoff : simulink/Logic and Bit Operations/Compare To Constant  relop=>=  const=ModelParam.motorMinThr  OutDataTypeStr=uint8
  Product : Product
  Sum1 : Sum  Inputs=++|
  Out5 : Outport  VectorParamsAs1DForOutWhenUnconnected=off
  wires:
  Minimum Throttle Cutoff/1 -> Product/2
  Product/1 -> Out5/1
  In5/1 -> Minimum Throttle Cutoff/1, Gain/1
  Gain/1 -> Sum1/2
  Sum1/1 -> Product/1
  Constant/1 -> Sum1/1

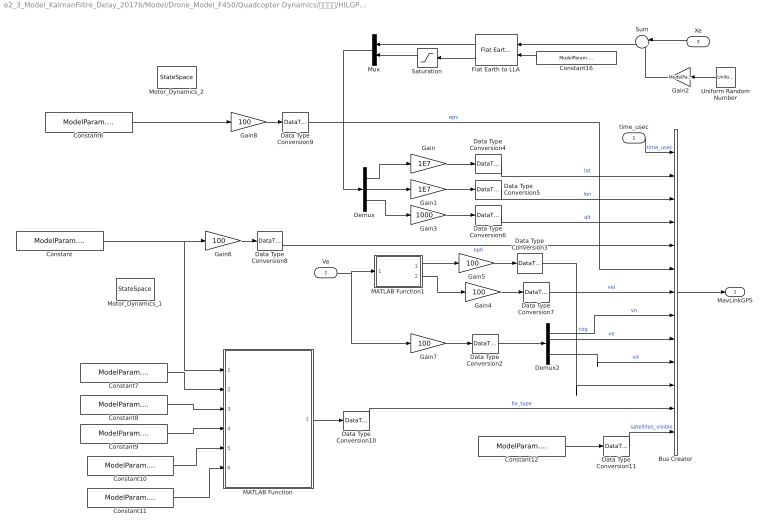
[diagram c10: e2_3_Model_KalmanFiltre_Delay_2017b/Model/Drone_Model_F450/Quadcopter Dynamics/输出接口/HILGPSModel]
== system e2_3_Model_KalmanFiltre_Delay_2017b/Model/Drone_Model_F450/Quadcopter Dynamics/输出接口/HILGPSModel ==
  time_usec : Inport
  Ve : Inport  Port=2
  Xe : Inport  Port=3
  Bus Creator : BusCreator  Inputs=13
  Constant : Constant  Value=ModelParam.GPSEphFinal
  Constant10 : Constant  Value=ModelParam.GPSFix2DFix
  Constant11 : Constant  Value=ModelParam.GPSFixNoFix
  Constant12 : Constant  Value=ModelParam.GPSSatsVisible
  Constant16 : Constant  Value=ModelParam.envAltitude
  Constant6 : Constant  Value=ModelParam.GPSEpvFinal
  Constant7 : Constant  Value=ModelParam.GPSEphMin3d
  Constant8 : Constant  Value=ModelParam.GPSEphMin2d
  Constant9 : Constant  Value=ModelParam.GPSFix3DFix
  Data Type Conversion10 : DataTypeConversion  OutDataTypeStr=uint8
  Data Type Conversion11 : DataTypeConversion  OutDataTypeStr=uint8
  Data Type Conversion2 : DataTypeConversion  OutDataTypeStr=int16
  Data Type Conversion{3,7..9} (4 alike) : DataTypeConversion  OutDataTypeStr=uint16
  Data Type Conversion4 : DataTypeConversion  OutDataTypeStr=int32
  Data Type Conversion5 : DataTypeConversion  OutDataTypeStr=int32
  Data Type Conversion6 : DataTypeConversion  OutDataTypeStr=int32
  Demux : Demux  Outputs=3
  Demux2 : Demux  Outputs=3
  Flat Earth to LLA : aerolibtransform2/Flat Earth to LLA  units=Metric (MKS)  ptype=Earth (WGS84)  F=1/298.257223563  R=6378137  LL0=[ModelParam.envLatitude ModelParam.envLongitude]  psi=0
  Gain : Gain  Gain=1E7
  Gain1 : Gain  Gain=1E7
  Gain2 : Gain  Gain=ModelParam.noiseUpperGPS
  Gain3 : Gain  Gain=1000
  Gain{4..8} (5 alike) : Gain  Gain=100
  MATLAB Function : MATLAB Function  TreatAsAtomicUnit=on
  MATLAB Function1 : MATLAB Function  TreatAsAtomicUnit=on
  Motor_Dynamics_1 : StateSpace  Commented=on  A=-1/ModelParam.GPSEphTimeConstant  C=1/ModelParam.GPSEphTimeConstant  D=0  InitialCondition=ModelParam.GPSEphInitial*ModelParam.GPSEphTimeConstant
  Motor_Dynamics_2 : StateSpace  Commented=on  A=-1/ModelParam.GPSEpvTimeConstant  C=1/ModelParam.GPSEpvTimeConstant  D=0  InitialCondition=ModelParam.GPSEpvInitial*ModelParam.GPSEpvTimeConstant
  Mux : Mux  Inputs=2
  Saturation : Saturate  UpperLimit=100000  LowerLimit=0
  Sum : Sum  Inputs=|++
  Uniform Random Number : UniformRandomNumber  Minimum=[-1,-1,-3]  Maximum=[1,1,3]  Seed=[14524,7875,698]  SampleTime=ModelParam.timeSamp
  MavLinkGPS : Outport  VectorParamsAs1DForOutWhenUnconnected=off
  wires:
  Data Type Conversion8/1 -> Bus Creator/5  "eph"
  Gain8/1 -> Data Type Conversion9/1
  Gain6/1 -> Data Type Conversion8/1
  Constant/1 -> MATLAB Function/1(eph), Gain6/1
  Data Type Conversion9/1 -> Bus Creator/6  "epv"
  time_usec/1 -> Bus Creator/1  "time_usec"
  Ve/1 -> Gain7/1, MATLAB Function1/1(u)
  Gain/1 -> Data Type Conversion4/1
  Gain1/1 -> Data Type Conversion5/1
  Gain3/1 -> Data Type Conversion6/1
  Data Type Conversion4/1 -> Bus Creator/2  "lat"
  Data Type Conversion5/1 -> Bus Creator/3  "lon"
  Data Type Conversion6/1 -> Bus Creator/4  "alt"
  Demux2/1 -> Bus Creator/8  "vn"
  Demux2/2 -> Bus Creator/9  "ve"
  Demux2/3 -> Bus Creator/10  "vd"
  Gain7/1 -> Data Type Conversion2/1
  Data Type Conversion2/1 -> Demux2/1
  Gain4/1 -> Data Type Conversion7/1
  MATLAB Function1/2(v) -> Gain4/1
  Data Type Conversion7/1 -> Bus Creator/7  "vel"
  Gain5/1 -> Data Type Conversion3/1
  MATLAB Function1/1(cot) -> Gain5/1
  Data Type Conversion3/1 -> Bus Creator/11  "cog"
  Constant9/1 -> MATLAB Function/4(Fix3D)
  Data Type Conversion11/1 -> Bus Creator/13  "satellites_visible"
  Constant7/1 -> MATLAB Function/2(eph3d)
  Data Type Conversion10/1 -> Bus Creator/12  "fix_type"
  MATLAB Function/1(FixType) -> Data Type Conversion10/1
  Constant8/1 -> MATLAB Function/3(eph2d)
  Bus Creator/1 -> MavLinkGPS/1
  Constant10/1 -> MATLAB Function/5(Fix2D)
  Constant11/1 -> MATLAB Function/6(FixNo)
  Constant12/1 -> Data Type Conversion11/1
  Flat Earth to LLA/2 -> Saturation/1
  Saturation/1 -> Mux/2
  Constant16/1 -> Flat Earth to LLA/2
  Mux/1 -> Demux/1
  Xe/1 -> Sum/1
  Flat Earth to LLA/1 -> Mux/1
  Demux/1 -> Gain/1
  Demux/2 -> Gain1/1
  Demux/3 -> Gain3/1
  Uniform Random Number/1 -> Gain2/1
  Sum/1 -> Flat Earth to LLA/1
  Gain2/1 -> Sum/2
  Constant6/1 -> Gain8/1

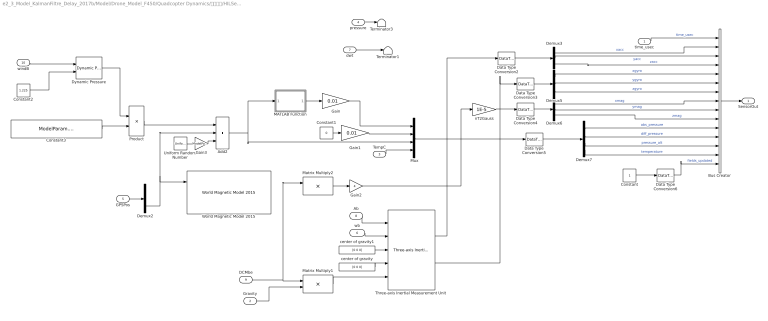
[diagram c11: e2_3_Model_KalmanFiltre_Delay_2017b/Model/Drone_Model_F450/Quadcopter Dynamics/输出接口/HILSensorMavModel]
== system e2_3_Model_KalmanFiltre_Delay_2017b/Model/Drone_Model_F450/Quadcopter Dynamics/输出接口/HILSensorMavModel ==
  time_usec : Inport
  Gravity : Inport  Port=2
  TempC : Inport  Port=3
  pressure : Inport  Port=4
  GPSPos : Inport  Port=5
  wb : Inport  Port=6
  dwt : Inport  Port=7
  Ab : Inport  Port=8
  DCMbe : Inport  Port=9
  windB : Inport  Port=10
  Add2 : Sum  Inputs=+++
  Bus Creator : BusCreator  Inputs=15
  Constant : Constant
  Constant1 : Constant  Value=0
  Constant2 : Constant  Value=1.225
  Constant3 : Constant  Value=ModelParam.noiseBaroCoupleWithSpeed
  Data Type Conversion{2..5} (4 alike) : DataTypeConversion  OutDataTypeStr=single
  Data Type Conversion6 : DataTypeConversion  OutDataTypeStr=uint32
  Demux{2..3,5..6} (4 alike) : Demux  Outputs=3
  Demux7 : Demux
  Dynamic Pressure : aerolibasang/Dynamic Pressure
  Gain : Gain  Gain=0.01
  Gain1 : Gain  Gain=0.01
  Gain2 : Gain  Gain=4
  Gain3 : Gain  Gain=ModelParam.noiseUpperBaro
  MATLAB Function : MATLAB Function  TreatAsAtomicUnit=on
  Matrix Multiply1 : Product  Multiplication=Matrix(*)
  Matrix Multiply2 : Product  Multiplication=Matrix(*)
  Mux : Mux
  Product : Product
  Terminator1 : Terminator
  Terminator3 : Terminator
  Three-axis Inertial Measurement Unit : aerolibnav/Three-axis Inertial Measurement Unit  units=Metric (MKS)  imu=[0 0 0]  i_Ts=0  dtype_a=off  w_a=190  z_a=0.707  a_sf_cc=[0.98 0 0; 0 0.98 0; 0 0 0.98]  a_bias=[0 0 0]  a_sat="[-19.62  -19.62  -19.62 19.62 19.62 19.62]"  dtype_g=off  w_g=190  z_g=0.707  g_sf_cc=[0.98 0 0; 0 0.98 0; 0 0 0.98]  g_bias=[0 0 0]  g_sens=[0 0 0]  g_sat="[-4.36  -4.36  -4.36 4.36 4.36 4.36]"  i_rand=off  i_seeds=[23093 23094 23095 23096 23097 23098]  i_pow=ModelParam.noisePowerIMU*[0.0000005 0.0000005 0.0000005 0.000000002 0.000000002 0.000000002]
  Uniform Random Number : UniformRandomNumber  Seed=15634  SampleTime=ModelParam.timeSamp
  World Magnetic Model 2015 : aerolibgravity2/World Magnetic Model 2015  units=Metric (MKS)  time_in=off  month=May  day=1  year=2017  action=Error  h_out=off  dec_out=off  inc_out=off  ti_out=off
  center of gravity : Constant  Value=[0 0 0]
  center of gravity1 : Constant  Value=[0 0 0]
  nT2Gauss : Gain  Gain=1E-5
  SensorOut : Outport  VectorParamsAs1DForOutWhenUnconnected=off
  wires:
  center of gravity/1 -> Three-axis Inertial Measurement Unit/4
  Demux3/3 -> Bus Creator/4  "zacc"
  Data Type Conversion3/1 -> Demux5/1
  Demux5/1 -> Bus Creator/5  "xgyro"
  nT2Gauss/1 -> Data Type Conversion4/1
  Data Type Conversion2/1 -> Demux3/1
  Demux3/2 -> Bus Creator/3  "yacc"
  Demux3/1 -> Bus Creator/2  "xacc"
  ? -> Matrix Multiply2/2
  Demux7/4 -> Bus Creator/14  "temperature"
  Demux5/3 -> Bus Creator/7  "zgyro"
  Data Type Conversion4/1 -> Demux6/1
  Demux6/1 -> Bus Creator/8  "xmag"
  Demux5/2 -> Bus Creator/6  "ygyro"
  Demux7/1 -> Bus Creator/11  "abs_pressure"
  Mux/1 -> Data Type Conversion5/1
  TempC/1 -> Mux/4
  Bus Creator/1 -> SensorOut/1
  Demux6/3 -> Bus Creator/10  "zmag"
  Data Type Conversion5/1 -> Demux7/1
  Demux6/2 -> Bus Creator/9  "ymag"
  Demux7/3 -> Bus Creator/13  "pressure_alt"
  Demux7/2 -> Bus Creator/12  "diff_pressure"
  GPSPos/1 -> Demux2/1
  Ab/1 -> Three-axis Inertial Measurement Unit/1
  time_usec/1 -> Bus Creator/1  "time_usec"
  Constant/1 -> Data Type Conversion6/1
  Data Type Conversion6/1 -> Bus Creator/15  "fields_updated"
  Gain/1 -> Mux/1
  Gain1/1 -> Mux/2
  Gravity/1 -> Matrix Multiply1/2
  DCMbe/1 -> Matrix Multiply1/1, Matrix Multiply2/1
  Matrix Multiply1/1 -> Three-axis Inertial Measurement Unit/5
  Three-axis Inertial Measurement Unit/1 -> Data Type Conversion2/1
  Three-axis Inertial Measurement Unit/2 -> Data Type Conversion3/1
  Demux2/1 -> ?
  Demux2/2 -> ?
  Demux2/3 -> Add2/2, World Magnetic Model 2015/1
  Add2/1 -> Mux/3, MATLAB Function/1(h)
  MATLAB Function/1(p) -> Gain/1
  pressure/1 -> Terminator3/1
  Constant1/1 -> Gain1/1
  Matrix Multiply2/1 -> Gain2/1
  Gain2/1 -> nT2Gauss/1
  wb/1 -> Three-axis Inertial Measurement Unit/2
  center of gravity1/1 -> Three-axis Inertial Measurement Unit/3
  dwt/1 -> Terminator1/1
  Uniform Random Number/1 -> Gain3/1
  windB/1 -> Dynamic Pressure/1
  Constant2/1 -> Dynamic Pressure/2
  Constant3/1 -> Product/2
  Dynamic Pressure/1 -> Product/1
  Product/1 -> Add2/1
  Gain3/1 -> Add2/3

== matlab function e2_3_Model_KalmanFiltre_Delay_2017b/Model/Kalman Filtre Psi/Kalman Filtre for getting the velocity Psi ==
function [Covariance_matrice,X_Kalmanfiltred] = fcn(Mesurement_Velocity) % Mesurement_State

% Persistent process for saving the last state and initilizing the variable
persistent P0_static;
if isempty(P0_static)
    P0_static=[[0.1,0 0;0,0.1,0;0 0 0.1] zeros(3) zeros(3) ;zeros(3) [0.1,0 0;0,0.1,0;0 0 0.1] zeros(3);zeros(3) zeros(3) [0.1,0 0;0,0.1,0;0 0 0.1]]; % the initilized matrice of estimated error
end

persistent Xkf_static;
if isempty(Xkf_static)
    Xkf_static=[0;0;0;0;0;0;0;0;0]; % the initilized state from Kalman Estimaton
end

% Determine the constants

% Simple time
Ts =0.01;

% Process Noise
p_var =0.05; % sigma
Q = eye(3)*p_var^2; % the covariance matrice of process noise
W=Q*randn(3,1);  % process noise
Q_delay=[Q zeros(3) zeros(3);zeros(3) Q zeros(3);zeros(3) zeros(3) Q];
% Mesurement Noise
m_var = 0.01; % sigma
R = [m_var^2 ];  % the covariance matrice of mesurement noise
V=R*randn; % mesurement noise
R_delay=R;
V_delay=R_delay*randn;
% Observation matrice
H=[1 0 0];
H_delay=[0 0 0 0 0 0 H];
% The indentity matrice
I=eye(3); 
I_delay=eye(9);

A=[1 Ts 0.5*(Ts^2);0 1 Ts;0 0 1];
A_delay=[A zeros(3) zeros(3);zeros(3) A zeros(3); zeros(3) zeros(3) A];
% Steady-State equation

% persistent X_real_static;
% if isempty(X_real_static)
%     X_real_static=[0;0]; % the initilized state from Kalman Estimaton
% end
% X_real_forward=X_real_static;
% X_real=A*X_real_forward+W;
% X_real_static=X_real;    
% Mesurement_Velocity=H_delay*(Mesurement_State)+V_delay;

%   Kalman Update process
    X_pre=A_delay*Xkf_static; % State estimation
    P_pre=A_delay*P0_static*A_delay'+Q_delay; % Covariance matrice estimation

    Kg=P_pre*H_delay'*inv(H_delay*P_pre*H_delay'+R_delay); % Kalman Gain calculation

    X_Kalmanfiltred=X_pre+Kg*(Mesurement_Velocity-H_delay*X_pre); % State estimation update
    Covariance_matrice=(I_delay-Kg*H_delay)*P_pre; % Covariance matrice estimation update

% update the value of the persistent variable for iterating the Kalman process
P0_static=Covariance_matrice;
Xkf_static=X_Kalmanfiltred;

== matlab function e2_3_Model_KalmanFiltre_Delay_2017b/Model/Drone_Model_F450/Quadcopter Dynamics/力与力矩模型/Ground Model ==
function [F1,M1,landed,takeoff] = fcn(mg,wb,Xe,Ve,Quet,terrainZ)
% This is a ground model that can provides reaction force and reaction torque

persistent z0;
if isempty(z0)
     z0=0;
end

persistent takeoffFlag;
if isempty(takeoffFlag)
     takeoffFlag=int8(0);
end

persistent landFlag;
if isempty(landFlag)
     landFlag=int8(1);
end


z=Xe(3)-z0;

 if (z<-0.3)&&(Ve(3)<-0.1)&&(takeoffFlag<0.5)
    takeoffFlag=int8(1);
    landFlag=int8(0);
 end
 
 if (z>-0.05)&&(Ve(3)>0.1)&&(landFlag<0.5)
    landFlag=int8(1);
    takeoffFlag=int8(0);
    z0=terrainZ;
 end

takeoff = takeoffFlag;
landed = landFlag;


F1=[0;0;0];
M1=[0;0;0];


if z>=0
    if Ve(3)>=1
        F1(3)=-mg(3)-1000*Ve(3);
    else
        F1(3)=-mg(3)-500*z-100*Ve(3);  
    end
    
    F1(1)=-10*Ve(1);
    F1(2)=-10*Ve(2);
    M1=-200*[Quet(2);Quet(3);Quet(4)]-10*wb;
end

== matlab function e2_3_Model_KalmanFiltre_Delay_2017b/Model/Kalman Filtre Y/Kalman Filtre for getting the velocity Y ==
function [Covariance_matrice,X_Kalmanfiltred] = fcn(Mesurement_Velocity) % Mesurement_State

% Persistent process for saving the last state and initilizing the variable
persistent P0_static;
if isempty(P0_static)
       P0_static=[[0.1,0 0;0,0.1,0;0 0 0.1] zeros(3) zeros(3) ;zeros(3) [0.1,0 0;0,0.1,0;0 0 0.1] zeros(3);zeros(3) zeros(3) [0.1,0 0;0,0.1,0;0 0 0.1]]; % the initilized matrice of estimated error 
end

persistent Xkf_static;
if isempty(Xkf_static)
    Xkf_static=[0;0;0;0;0;0;0;0;0]; % the initilized state from Kalman Estimaton
end

% Determine the constants

% Simple time
Ts =0.01;

% Process Noise
p_var =0.05; % sigma
Q = eye(3)*p_var^2; % the covariance matrice of process noise
W=Q*randn(3,1);  % process noise
Q_delay=[Q zeros(3) zeros(3);zeros(3) Q zeros(3);zeros(3) zeros(3) Q];
% Mesurement Noise
m_var = 0.01; % sigma
R = [m_var^2 ];  % the covariance matrice of mesurement noise
V=R*randn; % mesurement noise
R_delay=R;
V_delay=R_delay*randn;
% Observation matrice
H=[1 0 0];
H_delay=[0 0 0 0 0 0 H];
% The indentity matrice
I=eye(3); 
I_delay=eye(9);

A=[1 Ts 0.5*(Ts^2);0 1 Ts;0 0 1];
A_delay=[A zeros(3) zeros(3);zeros(3) A zeros(3); zeros(3) zeros(3) A];
% Steady-State equation

% persistent X_real_static;
% if isempty(X_real_static)
%     X_real_static=[0;0]; % the initilized state from Kalman Estimaton
% end
% X_real_forward=X_real_static;
% X_real=A*X_real_forward+W;
% X_real_static=X_real;    
% Mesurement_Velocity=H_delay*(Mesurement_State)+V_delay;

%   Kalman Update process
    X_pre=A_delay*Xkf_static; % State estimation
    P_pre=A_delay*P0_static*A_delay'+Q_delay; % Covariance matrice estimation

    Kg=P_pre*H_delay'*inv(H_delay*P_pre*H_delay'+R_delay); % Kalman Gain calculation

    X_Kalmanfiltred=X_pre+Kg*(Mesurement_Velocity-H_delay*X_pre); % State estimation update
    Covariance_matrice=(I_delay-Kg*H_delay)*P_pre; % Covariance matrice estimation update

% update the value of the persistent variable for iterating the Kalman process
P0_static=Covariance_matrice;
Xkf_static=X_Kalmanfiltred;

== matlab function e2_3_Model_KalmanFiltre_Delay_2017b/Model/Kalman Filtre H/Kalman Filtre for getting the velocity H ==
function [Covariance_matrice,X_Kalmanfiltred] = fcn(Mesurement_Velocity) % Mesurement_State

% Persistent process for saving the last state and initilizing the variable
persistent P0_static;
if isempty(P0_static)
    P0_static=[[0.1,0 0;0,0.1,0;0 0 0.1] zeros(3) zeros(3) ;zeros(3) [0.1,0 0;0,0.1,0;0 0 0.1] zeros(3);zeros(3) zeros(3) [0.1,0 0;0,0.1,0;0 0 0.1]]; % the initilized matrice of estimated error
end

persistent Xkf_static;
if isempty(Xkf_static)
    Xkf_static=[0;0;0;0;0;0;0;0;0]; % the initilized state from Kalman Estimaton
end

% Determine the constants

% Simple time
Ts =0.01;

% Process Noise
p_var =0.1; % sigma
Q = eye(3)*p_var^2; % the covariance matrice of process noise
W=Q*randn(3,1);  % process noise
Q_delay=[Q zeros(3) zeros(3);zeros(3) Q zeros(3);zeros(3) zeros(3) Q];
% Mesurement Noise
m_var = 0.01; % sigma
R = [m_var^2 ];  % the covariance matrice of mesurement noise
V=R*randn; % mesurement noise
R_delay=R;
V_delay=R_delay*randn;
% Observation matrice
H=[1 0 0];
H_delay=[0 0 0 0 0 0 H];
% The indentity matrice
I=eye(3); 
I_delay=eye(9);

A=[1 Ts 0.5*(Ts^2);0 1 Ts;0 0 1];
A_delay=[A zeros(3) zeros(3);zeros(3) A zeros(3); zeros(3) zeros(3) A];
% Steady-State equation

% persistent X_real_static;
% if isempty(X_real_static)
%     X_real_static=[0;0]; % the initilized state from Kalman Estimaton
% end
% X_real_forward=X_real_static;
% X_real=A*X_real_forward+W;
% X_real_static=X_real;    
% Mesurement_Velocity=H_delay*(Mesurement_State)+V_delay;

%   Kalman Update process
    X_pre=A_delay*Xkf_static; % State estimation
    P_pre=A_delay*P0_static*A_delay'+Q_delay; % Covariance matrice estimation

    Kg=P_pre*H_delay'*inv(H_delay*P_pre*H_delay'+R_delay); % Kalman Gain calculation

    X_Kalmanfiltred=X_pre+Kg*(Mesurement_Velocity-H_delay*X_pre); % State estimation update
    Covariance_matrice=(I_delay-Kg*H_delay)*P_pre; % Covariance matrice estimation update

% update the value of the persistent variable for iterating the Kalman process
P0_static=Covariance_matrice;
Xkf_static=X_Kalmanfiltred;

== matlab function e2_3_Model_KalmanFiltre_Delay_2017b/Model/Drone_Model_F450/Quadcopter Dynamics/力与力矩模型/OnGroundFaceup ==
function y = fcn(EulerAng)

targetRoll = 0;
% if cos(EulerAng(1))<0
%     targetRoll=pi;  
% end

targetPitch = 0;
% if cos(EulerAng(2))<0
%         targetPitch=pi;
% end
    
y = [targetRoll;targetPitch;EulerAng(3)];

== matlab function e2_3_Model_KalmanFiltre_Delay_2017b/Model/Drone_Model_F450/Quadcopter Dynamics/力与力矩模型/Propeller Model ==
function [Fb,Fd,Mb] = fcn(uavType,w,R,Cm,Ct,Jm,wb,Vb,Cd)
% This is control effectiveness model, where Fb is the force produced by motors, Mb is
% the moment produced by motors, and Fd is the resistance produced by the air.
% The gyroscopic torque is not considered here.

 %P=wb(1);Q=wb(2);

 switch uavType
     case 0
 %%叉字型
 M_rctcm = [-sin(pi/4)*R*Ct,sin(pi/4)*R*Ct,sin(pi/4)*R*Ct,-sin(pi/4)*R*Ct;sin(pi/4)*R*Ct,-sin(pi/4)*R*Ct,sin(pi/4)*R*Ct,-sin(pi/4)*R*Ct;Cm,Cm,-Cm,-Cm];
 %tau_motorGyro = [-Q*Jm*(w(1)+w(2)-w(3)-w(4)); P*Jm*(w(1)+w(2)-w(3)-w(4)); 0]; 
 Mb = M_rctcm*(w.^2);%+tau_motorGyro; 
     case 1
%%+字型
 M_rctcm = [-R*Ct,R*Ct,0,0;0,0,R*Ct,-R*Ct;Cm,Cm,-Cm,-Cm];
 %tau_motorGyro = [-Q*Jm*(w(1)+w(2)-w(3)-w(4)); P*Jm*(w(1)+w(2)-w(3)-w(4)); 0];
 Mb = M_rctcm*(w.^2);%+tau_motorGyro; 
     otherwise
      Mb = [0;0;0];    
 end
 
 Fb = [0; 0; -sum(Ct*(w.^2))]; 
 Fd = -Cd*Vb.*abs(Vb)*0.5;
end

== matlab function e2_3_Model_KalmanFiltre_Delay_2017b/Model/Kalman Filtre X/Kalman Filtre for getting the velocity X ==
function [Covariance_matrice,X_Kalmanfiltred] = fcn(Mesurement_Velocity) % Mesurement_State

% Persistent process for saving the last state and initilizing the variable
persistent P0_static;
if isempty(P0_static)
    P0_static=[[0.1,0 0;0,0.1,0;0 0 0.1] zeros(3) zeros(3) ;zeros(3) [0.1,0 0;0,0.1,0;0 0 0.1] zeros(3);zeros(3) zeros(3) [0.1,0 0;0,0.1,0;0 0 0.1]]; % the initilized matrice of estimated error
end

persistent Xkf_static;
if isempty(Xkf_static)
    Xkf_static=[0;0;0;0;0;0;0;0;0]; % the initilized state from Kalman Estimaton
end

% Determine the constants

% Simple time
Ts =0.01;

% Process Noise
p_var =0.05; % sigma
Q = eye(3)*p_var^2; % the covariance matrice of process noise
W=Q*randn(3,1);  % process noise
Q_delay=[Q zeros(3) zeros(3);zeros(3) Q zeros(3);zeros(3) zeros(3) Q];
% Mesurement Noise
m_var = 0.01; % sigma
R = [m_var^2 ];  % the covariance matrice of mesurement noise
V=R*randn; % mesurement noise
R_delay=R;
V_delay=R_delay*randn;
% Observation matrice
H=[1 0 0];
H_delay=[0 0 0 0 0 0 H];
% The indentity matrice
I=eye(3); 
I_delay=eye(9);

A=[1 Ts 0.5*(Ts^2);0 1 Ts;0 0 1];
A_delay=[A zeros(3) zeros(3);zeros(3) A zeros(3); zeros(3) zeros(3) A];
% Steady-State equation

% persistent X_real_static;
% if isempty(X_real_static)
%     X_real_static=[0;0]; % the initilized state from Kalman Estimaton
% end
% X_real_forward=X_real_static;
% X_real=A*X_real_forward+W;
% X_real_static=X_real;    
% Mesurement_Velocity=H_delay*(Mesurement_State)+V_delay;

%   Kalman Update process
    X_pre=A_delay*Xkf_static; % State estimation
    P_pre=A_delay*P0_static*A_delay'+Q_delay; % Covariance matrice estimation

    Kg=P_pre*H_delay'*inv(H_delay*P_pre*H_delay'+R_delay); % Kalman Gain calculation

    X_Kalmanfiltred=X_pre+Kg*(Mesurement_Velocity-H_delay*X_pre); % State estimation update
    Covariance_matrice=(I_delay-Kg*H_delay)*P_pre; % Covariance matrice estimation update

% update the value of the persistent variable for iterating the Kalman process
P0_static=Covariance_matrice;
Xkf_static=X_Kalmanfiltred;

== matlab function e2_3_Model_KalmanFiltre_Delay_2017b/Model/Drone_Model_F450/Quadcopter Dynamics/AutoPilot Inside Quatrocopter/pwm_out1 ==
function [M1, M2, M3, M4] = motor_mixer(Roll, Pitch, Yaw, Thrust)

idle_PWM = 1000;

% Quad XROLL （根据QP里面的叉字形结构的文字）
% M1 = ((Pitch+ Yaw)+Thrust-Roll) * 1000 + idle_PWM;
 %M2 = ((Pitch - Yaw)+Thrust+Roll) * 1000 + idle_PWM;
 %M3 = ((Roll +Yaw) + Thrust-Pitch) * 1000 + idle_PWM;
 %M4 = ((-Roll - Pitch-Yaw) + Thrust) * 1000 + idle_PWM;
% M5 = 1000;
% M6 = 1000;
% M7 = 1000;
% M8 = 1000;
%qp上实际的输出
M1 = (Thrust+Pitch-Roll+Yaw)*1000  + idle_PWM;
M2 = (Thrust-Pitch +Roll+Yaw)*1000 + idle_PWM;
M3 = (Thrust+Roll+Pitch-Yaw)*1000  + idle_PWM;
M4 = (Thrust-Roll- Pitch -Yaw)*1000 + idle_PWM;
% Quad +
 %M1 = ((Pitch - Yaw) * Thrust / 2 + Thrust) * 1000 + idle_PWM;
 %M2 = ((-Roll + Yaw) * Thrust / 2 + Thrust) * 1000 + idle_PWM;
% M3 = ((-Pitch - Yaw) * Thrust / 2 + Thrust) * 1000 + idle_PWM;
 %M4 = ((Roll + Yaw) * Thrust / 2 + Thrust) * 1000 + idle_PWM;
% M5 = 1000;
% M6 = 1000;
% M7 = 1000;
% M8 = 1000;

% Hex X
% M1 = ((Pitch + Roll / 2 - Yaw) * Thrust / 2 + Thrust) * 1000 + idle_PWM;
% M2 = ((Pitch - Roll / 2 + Yaw) * Thrust / 2 + Thrust) * 1000 + idle_PWM;
% M3 = ((-Roll - Yaw) * Thrust / 2 + Thrust) * 1000 + idle_PWM;
% M4 = ((-Pitch - Roll / 2 + Yaw) * Thrust / 2 + Thrust) * 1000 + idle_PWM;
% M5 = ((-Pitch + Roll / 2 - Yaw) * Thrust / 2 + Thrust) * 1000 + idle_PWM;
% M6 = ((Roll + Yaw) * Thrust / 2 + Thrust) * 1000 + idle_PWM;
% M7 = 1000;
% M8 = 1000;

% Hex X (From Adam)
%M1 = uint16(single(((-Roll - Yaw) * Thrust / 3 + Thrust) * single(1000))) + idle_PWM;
%M2 = uint16(single(((Roll + Yaw) * Thrust / 3 + Thrust) * single(1000))) + idle_PWM;
%M3 = uint16(single(((Pitch + (Roll / 2) - Yaw) * Thrust / 3 + Thrust) * single(1000))) + idle_PWM;
%M4 = uint16(single(((-Pitch - (Roll / 2) + Yaw) * Thrust / 3 + Thrust) * single(1000))) + idle_PWM;
%M5 = uint16(single(((Pitch - (Roll / 2) + Yaw) * Thrust / 3 + Thrust) * single(1000))) + idle_PWM;
%M6 = uint16(single(((-Pitch + (Roll / 2) - Yaw) * Thrust / 3 + Thrust) * single(1000))) + idle_PWM;

% Hex X (Version 2)
% Roll/Yaw
% M1 = ((-Roll - Yaw) * Thrust / 2 + Thrust) * 1000 + idle_PWM;
% M2 = ((Roll + Yaw) * Thrust / 2 + Thrust) * 1000 + idle_PWM;
% % + Pitch/Roll
% M6 = ((Pitch + Roll / 2 - Yaw) * Thrust / 2 + Thrust) * 1000 + idle_PWM;
% M4 = ((Pitch - Roll / 2 + Yaw) * Thrust / 2 + Thrust) * 1000 + idle_PWM;
% % - Pitch/Roll
% M5 = ((-Pitch - Roll / 2 + Yaw) * Thrust / 2 + Thrust) * 1000 + idle_PWM;
% M3 = ((-Pitch + Roll / 2 - Yaw) * Thrust / 2 + Thrust) * 1000 + idle_PWM;

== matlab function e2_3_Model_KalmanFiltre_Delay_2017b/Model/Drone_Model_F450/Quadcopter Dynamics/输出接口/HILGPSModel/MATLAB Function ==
function FixType = fcn(eph,eph3d,eph2d,Fix3D,Fix2D,FixNo)
if eph <= eph3d
    FixType=Fix3D;
elseif eph <= eph2d
    FixType=Fix2D;
else
    FixType=FixNo;
end

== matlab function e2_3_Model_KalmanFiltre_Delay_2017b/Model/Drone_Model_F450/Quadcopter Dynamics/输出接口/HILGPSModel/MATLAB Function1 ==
function [cot,v] = Ang360(u)
 cot=atan2d(u(2),u(1));
if cot<0
    cot=cot+360;
end

v=norm(u);

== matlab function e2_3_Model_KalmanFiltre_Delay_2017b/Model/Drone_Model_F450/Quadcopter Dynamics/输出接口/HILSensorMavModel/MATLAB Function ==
function p = fcn(h)
p=((1-h/0.3048/145366.45))^(1/0.190284)*101325;

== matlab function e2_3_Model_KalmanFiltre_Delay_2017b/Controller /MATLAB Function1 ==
function [theta,phi] = fcn(eax,eay)
g=9.8;

theta =-eax/g;% vx
phi =eay/g;% vy

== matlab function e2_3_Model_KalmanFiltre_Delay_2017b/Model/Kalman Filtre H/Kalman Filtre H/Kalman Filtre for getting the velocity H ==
function [Covariance_matrice,X_Kalmanfiltred] = fcn(Mesurement_Velocity)

% Persistent process for saving the last state and initilizing the variable
persistent P0_static;
if isempty(P0_static)
    P0_static=[0.1,0 0;0,0.1,0;0 0 0.1]; % the initilized matrice of estimated error
end

persistent Xkf_static;
if isempty(Xkf_static)
    Xkf_static=[0;0;0]; % the initilized state from Kalman Estimaton
end

% Determine the constants

% Simple time
Ts =0.01;

% Process Noise
p_var =0.05; % sigma
Q = eye(3)*p_var^2; % the covariance matrice of process noise
W=Q*randn(3,1);  % process noise

% Mesurement Noise
m_var = 0.01; % sigma
R = [m_var^2 ];  % the covariance matrice of mesurement noise
V=R*randn; % mesurement noise

% Observation matrice
H=[1 0 0];

% The indentity matrice
I=eye(3); 

% State Transition Martrix
A=[1 Ts 0.5*(Ts^2);0 1 Ts;0 0 1];

% Steady-State equation

% persistent X_real_static;
% if isempty(X_real_static)
%     X_real_static=[0;0]; % the initilized state from Kalman Estimaton
% end
% X_real_forward=X_real_static;
% X_real=A*X_real_forward+W;
% Mesurement_Velocity=H*(X_real)+V;
% X_real_static=X_real;    

%   Kalman Update process
    X_pre=A*Xkf_static; % State estimation
    P_pre=A*P0_static*A'+Q; % Covariance matrice estimation

    Kg=P_pre*H'*inv(H*P_pre*H'+R); % Kalman Gain calculation

    X_Kalmanfiltred=X_pre+Kg*(Mesurement_Velocity-H*X_pre); % State estimation update
    Covariance_matrice=(I-Kg*H)*P_pre; % Covariance matrice estimation update

% update the value of the persistent variable for iterating the Kalman process
P0_static=Covariance_matrice;
Xkf_static=X_Kalmanfiltred;

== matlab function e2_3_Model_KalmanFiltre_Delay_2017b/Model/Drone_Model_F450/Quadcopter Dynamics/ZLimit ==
function Xee = fcn(zt,xe)
Xee=xe;
if Xee(3)>zt
    Xee(3)=zt;
end

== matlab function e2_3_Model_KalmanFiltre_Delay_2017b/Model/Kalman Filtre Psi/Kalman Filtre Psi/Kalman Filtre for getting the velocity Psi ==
function [Covariance_matrice,X_Kalmanfiltred] = fcn(Mesurement_Velocity)

% Persistent process for saving the last state and initilizing the variable
persistent P0_static;
if isempty(P0_static)
    P0_static=[0.1,0 0;0,0.1,0;0 0 0.1]; % the initilized matrice of estimated error
end

persistent Xkf_static;
if isempty(Xkf_static)
    Xkf_static=[0;0;0]; % the initilized state from Kalman Estimaton
end

% Determine the constants

% Simple time
Ts =0.01;

% Process Noise
p_var =0.01; % sigma
Q = eye(3)*p_var^2; % the covariance matrice of process noise
W=Q*randn(3,1);  % process noise

% Mesurement Noise
m_var = 0.05; % sigma
R = [m_var^2 ];  % the covariance matrice of mesurement noise
V=R*randn; % mesurement noise

% Observation matrice
H=[1 0 0];

% The indentity matrice
I=eye(3); 

% State Transition Martrix
A=[1 Ts 0.5*(Ts^2);0 1 Ts;0 0 1];


% Steady-State equation

% persistent X_real_static;
% if isempty(X_real_static)
%     X_real_static=[0;0]; % the initilized state from Kalman Estimaton
% end
% X_real_forward=X_real_static;
% X_real=A*X_real_forward+W;
% Mesurement_Velocity=H*(X_real)+V;
% X_real_static=X_real;    

%   Kalman Update process
    X_pre=A*Xkf_static; % State estimation
    P_pre=A*P0_static*A'+Q; % Covariance matrice estimation

    Kg=P_pre*H'*inv(H*P_pre*H'+R); % Kalman Gain calculation

    X_Kalmanfiltred=X_pre+Kg*(Mesurement_Velocity-H*X_pre); % State estimation update
    Covariance_matrice=(I-Kg*H)*P_pre; % Covariance matrice estimation update

% update the value of the persistent variable for iterating the Kalman process
P0_static=Covariance_matrice;
Xkf_static=X_Kalmanfiltred;

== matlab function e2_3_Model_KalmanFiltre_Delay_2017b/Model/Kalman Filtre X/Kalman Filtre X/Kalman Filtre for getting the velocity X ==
function [Covariance_matrice,X_Kalmanfiltred] = fcn(Mesurement_Velocity)

% Persistent process for saving the last state and initilizing the variable
persistent P0_static;
if isempty(P0_static)
    P0_static=[0.1,0 0;0,0.1,0;0 0 0.1]; % the initilized matrice of estimated error
end

persistent Xkf_static;
if isempty(Xkf_static)
    Xkf_static=[0;0;0]; % the initilized state from Kalman Estimaton
end

% Determine the constants

% Simple time
Ts =0.01;

% Process Noise
p_var =0.05; % sigma
Q = eye(3)*p_var^2; % the covariance matrice of process noise
W=Q*randn(3,1);  % process noise

% Mesurement Noise
m_var = 0.01; % sigma
R = [m_var^2 ];  % the covariance matrice of mesurement noise
V=R*randn; % mesurement noise

% Observation matrice
H=[1 0 0];

% The indentity matrice
I=eye(3); 

% State Transition Martrix
A=[1 Ts 0.5*(Ts^2);0 1 Ts;0 0 1];

% Steady-State equation

% persistent X_real_static;
% if isempty(X_real_static)
%     X_real_static=[0;0]; % the initilized state from Kalman Estimaton
% end
% X_real_forward=X_real_static;
% X_real=A*X_real_forward+W;
% Mesurement_Velocity=H*(X_real)+V;
% X_real_static=X_real;    

%   Kalman Update process
    X_pre=A*Xkf_static; % State estimation
    P_pre=A*P0_static*A'+Q; % Covariance matrice estimation

    Kg=P_pre*H'*inv(H*P_pre*H'+R); % Kalman Gain calculation

    X_Kalmanfiltred=X_pre+Kg*(Mesurement_Velocity-H*X_pre); % State estimation update
    Covariance_matrice=(I-Kg*H)*P_pre; % Covariance matrice estimation update

% update the value of the persistent variable for iterating the Kalman process
P0_static=Covariance_matrice;
Xkf_static=X_Kalmanfiltred;

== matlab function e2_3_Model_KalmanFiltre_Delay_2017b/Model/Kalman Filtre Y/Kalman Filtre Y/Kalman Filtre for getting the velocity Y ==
function [Covariance_matrice,X_Kalmanfiltred] = fcn(Mesurement_Velocity)

% Persistent process for saving the last state and initilizing the variable
persistent P0_static;
if isempty(P0_static)
    P0_static=[0.1,0 0;0,0.1,0;0 0 0.1]; % the initilized matrice of estimated error
end

persistent Xkf_static;
if isempty(Xkf_static)
    Xkf_static=[0;0;0]; % the initilized state from Kalman Estimaton
end

% Determine the constants

% Simple time
Ts =0.01;

% Process Noise
p_var =0.05; % sigma
Q = eye(3)*p_var^2; % the covariance matrice of process noise
W=Q*randn(3,1);  % process noise

% Mesurement Noise
m_var =0.01; % sigma
R = [m_var^2 ];  % the covariance matrice of mesurement noise
V=R*randn; % mesurement noise

% Observation matrice
H=[1 0 0];

% The indentity matrice
I=eye(3); 

% State Transition Martrix
A=[1 Ts 0.5*(Ts^2);0 1 Ts;0 0 1];

% Steady-State equation

% persistent X_real_static;
% if isempty(X_real_static)
%     X_real_static=[0;0]; % the initilized state from Kalman Estimaton
% end
% X_real_forward=X_real_static;
% X_real=A*X_real_forward+W;
% Mesurement_Velocity=H*(X_real)+V;
% X_real_static=X_real;    

%   Kalman Update process
    X_pre=A*Xkf_static; % State estimation
    P_pre=A*P0_static*A'+Q; % Covariance matrice estimation

    Kg=P_pre*H'*inv(H*P_pre*H'+R); % Kalman Gain calculation

    X_Kalmanfiltred=X_pre+Kg*(Mesurement_Velocity-H*X_pre); % State estimation update
    Covariance_matrice=(I-Kg*H)*P_pre; % Covariance matrice estimation update

% update the value of the persistent variable for iterating the Kalman process
P0_static=Covariance_matrice;
Xkf_static=X_Kalmanfiltred;
